VERSION 5.7 ;
BUSBITCHARS "[]" ;
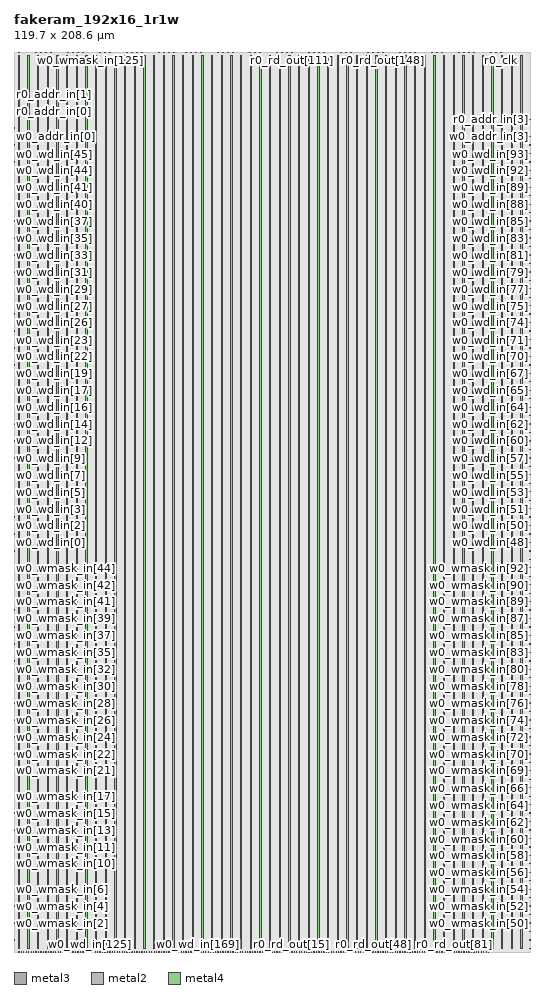
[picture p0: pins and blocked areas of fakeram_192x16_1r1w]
MACRO fakeram_192x16_1r1w
  FOREIGN fakeram_192x16_1r1w 0 0 ;
  SYMMETRY X Y R90 ;
  SIZE 119.700 BY 208.600 ;
  CLASS BLOCK ;
  PIN w0_wmask_in[0]
    DIRECTION INPUT ;
    USE SIGNAL ;
    SHAPE ABUTMENT ;
    PORT
      LAYER metal3 ;
      RECT 0.000 0.805 0.210 0.875 ;
    END
  END w0_wmask_in[0]
  PIN w0_wmask_in[1]
    DIRECTION INPUT ;
    USE SIGNAL ;
    SHAPE ABUTMENT ;
    PORT
      LAYER metal3 ;
      RECT 0.000 2.765 0.210 2.835 ;
    END
  END w0_wmask_in[1]
  PIN w0_wmask_in[2]
    DIRECTION INPUT ;
    USE SIGNAL ;
    SHAPE ABUTMENT ;
    PORT
      LAYER metal3 ;
      RECT 0.000 4.725 0.210 4.795 ;
    END
  END w0_wmask_in[2]
  PIN w0_wmask_in[3]
    DIRECTION INPUT ;
    USE SIGNAL ;
    SHAPE ABUTMENT ;
    PORT
      LAYER metal3 ;
      RECT 0.000 6.685 0.210 6.755 ;
    END
  END w0_wmask_in[3]
  PIN w0_wmask_in[4]
    DIRECTION INPUT ;
    USE SIGNAL ;
    SHAPE ABUTMENT ;
    PORT
      LAYER metal3 ;
      RECT 0.000 8.645 0.210 8.715 ;
    END
  END w0_wmask_in[4]
  PIN w0_wmask_in[5]
    DIRECTION INPUT ;
    USE SIGNAL ;
    SHAPE ABUTMENT ;
    PORT
      LAYER metal3 ;
      RECT 0.000 10.605 0.210 10.675 ;
    END
  END w0_wmask_in[5]
  PIN w0_wmask_in[6]
    DIRECTION INPUT ;
    USE SIGNAL ;
    SHAPE ABUTMENT ;
    PORT
      LAYER metal3 ;
      RECT 0.000 12.565 0.210 12.635 ;
    END
  END w0_wmask_in[6]
  PIN w0_wmask_in[7]
    DIRECTION INPUT ;
    USE SIGNAL ;
    SHAPE ABUTMENT ;
    PORT
      LAYER metal3 ;
      RECT 0.000 14.525 0.210 14.595 ;
    END
  END w0_wmask_in[7]
  PIN w0_wmask_in[8]
    DIRECTION INPUT ;
    USE SIGNAL ;
    SHAPE ABUTMENT ;
    PORT
      LAYER metal3 ;
      RECT 0.000 16.485 0.210 16.555 ;
    END
  END w0_wmask_in[8]
  PIN w0_wmask_in[9]
    DIRECTION INPUT ;
    USE SIGNAL ;
    SHAPE ABUTMENT ;
    PORT
      LAYER metal3 ;
      RECT 0.000 18.445 0.210 18.515 ;
    END
  END w0_wmask_in[9]
  PIN w0_wmask_in[10]
    DIRECTION INPUT ;
    USE SIGNAL ;
    SHAPE ABUTMENT ;
    PORT
      LAYER metal3 ;
      RECT 0.000 20.405 0.210 20.475 ;
    END
  END w0_wmask_in[10]
  PIN w0_wmask_in[11]
    DIRECTION INPUT ;
    USE SIGNAL ;
    SHAPE ABUTMENT ;
    PORT
      LAYER metal3 ;
      RECT 0.000 22.365 0.210 22.435 ;
    END
  END w0_wmask_in[11]
  PIN w0_wmask_in[12]
    DIRECTION INPUT ;
    USE SIGNAL ;
    SHAPE ABUTMENT ;
    PORT
      LAYER metal3 ;
      RECT 0.000 24.325 0.210 24.395 ;
    END
  END w0_wmask_in[12]
  PIN w0_wmask_in[13]
    DIRECTION INPUT ;
    USE SIGNAL ;
    SHAPE ABUTMENT ;
    PORT
      LAYER metal3 ;
      RECT 0.000 26.285 0.210 26.355 ;
    END
  END w0_wmask_in[13]
  PIN w0_wmask_in[14]
    DIRECTION INPUT ;
    USE SIGNAL ;
    SHAPE ABUTMENT ;
    PORT
      LAYER metal3 ;
      RECT 0.000 28.245 0.210 28.315 ;
    END
  END w0_wmask_in[14]
  PIN w0_wmask_in[15]
    DIRECTION INPUT ;
    USE SIGNAL ;
    SHAPE ABUTMENT ;
    PORT
      LAYER metal3 ;
      RECT 0.000 30.205 0.210 30.275 ;
    END
  END w0_wmask_in[15]
  PIN w0_wmask_in[16]
    DIRECTION INPUT ;
    USE SIGNAL ;
    SHAPE ABUTMENT ;
    PORT
      LAYER metal3 ;
      RECT 0.000 32.165 0.210 32.235 ;
    END
  END w0_wmask_in[16]
  PIN w0_wmask_in[17]
    DIRECTION INPUT ;
    USE SIGNAL ;
    SHAPE ABUTMENT ;
    PORT
      LAYER metal3 ;
      RECT 0.000 34.125 0.210 34.195 ;
    END
  END w0_wmask_in[17]
  PIN w0_wmask_in[18]
    DIRECTION INPUT ;
    USE SIGNAL ;
    SHAPE ABUTMENT ;
    PORT
      LAYER metal3 ;
      RECT 0.000 36.085 0.210 36.155 ;
    END
  END w0_wmask_in[18]
  PIN w0_wmask_in[19]
    DIRECTION INPUT ;
    USE SIGNAL ;
    SHAPE ABUTMENT ;
    PORT
      LAYER metal3 ;
      RECT 0.000 38.045 0.210 38.115 ;
    END
  END w0_wmask_in[19]
  PIN w0_wmask_in[20]
    DIRECTION INPUT ;
    USE SIGNAL ;
    SHAPE ABUTMENT ;
    PORT
      LAYER metal3 ;
      RECT 0.000 40.005 0.210 40.075 ;
    END
  END w0_wmask_in[20]
  PIN w0_wmask_in[21]
    DIRECTION INPUT ;
    USE SIGNAL ;
    SHAPE ABUTMENT ;
    PORT
      LAYER metal3 ;
      RECT 0.000 41.965 0.210 42.035 ;
    END
  END w0_wmask_in[21]
  PIN w0_wmask_in[22]
    DIRECTION INPUT ;
    USE SIGNAL ;
    SHAPE ABUTMENT ;
    PORT
      LAYER metal3 ;
      RECT 0.000 43.925 0.210 43.995 ;
    END
  END w0_wmask_in[22]
  PIN w0_wmask_in[23]
    DIRECTION INPUT ;
    USE SIGNAL ;
    SHAPE ABUTMENT ;
    PORT
      LAYER metal3 ;
      RECT 0.000 45.885 0.210 45.955 ;
    END
  END w0_wmask_in[23]
  PIN w0_wmask_in[24]
    DIRECTION INPUT ;
    USE SIGNAL ;
    SHAPE ABUTMENT ;
    PORT
      LAYER metal3 ;
      RECT 0.000 47.845 0.210 47.915 ;
    END
  END w0_wmask_in[24]
  PIN w0_wmask_in[25]
    DIRECTION INPUT ;
    USE SIGNAL ;
    SHAPE ABUTMENT ;
    PORT
      LAYER metal3 ;
      RECT 0.000 49.805 0.210 49.875 ;
    END
  END w0_wmask_in[25]
  PIN w0_wmask_in[26]
    DIRECTION INPUT ;
    USE SIGNAL ;
    SHAPE ABUTMENT ;
    PORT
      LAYER metal3 ;
      RECT 0.000 51.765 0.210 51.835 ;
    END
  END w0_wmask_in[26]
  PIN w0_wmask_in[27]
    DIRECTION INPUT ;
    USE SIGNAL ;
    SHAPE ABUTMENT ;
    PORT
      LAYER metal3 ;
      RECT 0.000 53.725 0.210 53.795 ;
    END
  END w0_wmask_in[27]
  PIN w0_wmask_in[28]
    DIRECTION INPUT ;
    USE SIGNAL ;
    SHAPE ABUTMENT ;
    PORT
      LAYER metal3 ;
      RECT 0.000 55.685 0.210 55.755 ;
    END
  END w0_wmask_in[28]
  PIN w0_wmask_in[29]
    DIRECTION INPUT ;
    USE SIGNAL ;
    SHAPE ABUTMENT ;
    PORT
      LAYER metal3 ;
      RECT 0.000 57.645 0.210 57.715 ;
    END
  END w0_wmask_in[29]
  PIN w0_wmask_in[30]
    DIRECTION INPUT ;
    USE SIGNAL ;
    SHAPE ABUTMENT ;
    PORT
      LAYER metal3 ;
      RECT 0.000 59.605 0.210 59.675 ;
    END
  END w0_wmask_in[30]
  PIN w0_wmask_in[31]
    DIRECTION INPUT ;
    USE SIGNAL ;
    SHAPE ABUTMENT ;
    PORT
      LAYER metal3 ;
      RECT 0.000 61.565 0.210 61.635 ;
    END
  END w0_wmask_in[31]
  PIN w0_wmask_in[32]
    DIRECTION INPUT ;
    USE SIGNAL ;
    SHAPE ABUTMENT ;
    PORT
      LAYER metal3 ;
      RECT 0.000 63.525 0.210 63.595 ;
    END
  END w0_wmask_in[32]
  PIN w0_wmask_in[33]
    DIRECTION INPUT ;
    USE SIGNAL ;
    SHAPE ABUTMENT ;
    PORT
      LAYER metal3 ;
      RECT 0.000 65.485 0.210 65.555 ;
    END
  END w0_wmask_in[33]
  PIN w0_wmask_in[34]
    DIRECTION INPUT ;
    USE SIGNAL ;
    SHAPE ABUTMENT ;
    PORT
      LAYER metal3 ;
      RECT 0.000 67.445 0.210 67.515 ;
    END
  END w0_wmask_in[34]
  PIN w0_wmask_in[35]
    DIRECTION INPUT ;
    USE SIGNAL ;
    SHAPE ABUTMENT ;
    PORT
      LAYER metal3 ;
      RECT 0.000 69.405 0.210 69.475 ;
    END
  END w0_wmask_in[35]
  PIN w0_wmask_in[36]
    DIRECTION INPUT ;
    USE SIGNAL ;
    SHAPE ABUTMENT ;
    PORT
      LAYER metal3 ;
      RECT 0.000 71.365 0.210 71.435 ;
    END
  END w0_wmask_in[36]
  PIN w0_wmask_in[37]
    DIRECTION INPUT ;
    USE SIGNAL ;
    SHAPE ABUTMENT ;
    PORT
      LAYER metal3 ;
      RECT 0.000 73.325 0.210 73.395 ;
    END
  END w0_wmask_in[37]
  PIN w0_wmask_in[38]
    DIRECTION INPUT ;
    USE SIGNAL ;
    SHAPE ABUTMENT ;
    PORT
      LAYER metal3 ;
      RECT 0.000 75.285 0.210 75.355 ;
    END
  END w0_wmask_in[38]
  PIN w0_wmask_in[39]
    DIRECTION INPUT ;
    USE SIGNAL ;
    SHAPE ABUTMENT ;
    PORT
      LAYER metal3 ;
      RECT 0.000 77.245 0.210 77.315 ;
    END
  END w0_wmask_in[39]
  PIN w0_wmask_in[40]
    DIRECTION INPUT ;
    USE SIGNAL ;
    SHAPE ABUTMENT ;
    PORT
      LAYER metal3 ;
      RECT 0.000 79.205 0.210 79.275 ;
    END
  END w0_wmask_in[40]
  PIN w0_wmask_in[41]
    DIRECTION INPUT ;
    USE SIGNAL ;
    SHAPE ABUTMENT ;
    PORT
      LAYER metal3 ;
      RECT 0.000 81.165 0.210 81.235 ;
    END
  END w0_wmask_in[41]
  PIN w0_wmask_in[42]
    DIRECTION INPUT ;
    USE SIGNAL ;
    SHAPE ABUTMENT ;
    PORT
      LAYER metal3 ;
      RECT 0.000 83.125 0.210 83.195 ;
    END
  END w0_wmask_in[42]
  PIN w0_wmask_in[43]
    DIRECTION INPUT ;
    USE SIGNAL ;
    SHAPE ABUTMENT ;
    PORT
      LAYER metal3 ;
      RECT 0.000 85.085 0.210 85.155 ;
    END
  END w0_wmask_in[43]
  PIN w0_wmask_in[44]
    DIRECTION INPUT ;
    USE SIGNAL ;
    SHAPE ABUTMENT ;
    PORT
      LAYER metal3 ;
      RECT 0.000 87.045 0.210 87.115 ;
    END
  END w0_wmask_in[44]
  PIN w0_wmask_in[45]
    DIRECTION INPUT ;
    USE SIGNAL ;
    SHAPE ABUTMENT ;
    PORT
      LAYER metal3 ;
      RECT 0.000 89.005 0.210 89.075 ;
    END
  END w0_wmask_in[45]
  PIN w0_wmask_in[46]
    DIRECTION INPUT ;
    USE SIGNAL ;
    SHAPE ABUTMENT ;
    PORT
      LAYER metal3 ;
      RECT 0.000 90.965 0.210 91.035 ;
    END
  END w0_wmask_in[46]
  PIN w0_wmask_in[47]
    DIRECTION INPUT ;
    USE SIGNAL ;
    SHAPE ABUTMENT ;
    PORT
      LAYER metal3 ;
      RECT 0.000 92.925 0.210 92.995 ;
    END
  END w0_wmask_in[47]
  PIN w0_wmask_in[48]
    DIRECTION INPUT ;
    USE SIGNAL ;
    SHAPE ABUTMENT ;
    PORT
      LAYER metal3 ;
      RECT 119.490 0.805 119.700 0.875 ;
    END
  END w0_wmask_in[48]
  PIN w0_wmask_in[49]
    DIRECTION INPUT ;
    USE SIGNAL ;
    SHAPE ABUTMENT ;
    PORT
      LAYER metal3 ;
      RECT 119.490 2.765 119.700 2.835 ;
    END
  END w0_wmask_in[49]
  PIN w0_wmask_in[50]
    DIRECTION INPUT ;
    USE SIGNAL ;
    SHAPE ABUTMENT ;
    PORT
      LAYER metal3 ;
      RECT 119.490 4.725 119.700 4.795 ;
    END
  END w0_wmask_in[50]
  PIN w0_wmask_in[51]
    DIRECTION INPUT ;
    USE SIGNAL ;
    SHAPE ABUTMENT ;
    PORT
      LAYER metal3 ;
      RECT 119.490 6.685 119.700 6.755 ;
    END
  END w0_wmask_in[51]
  PIN w0_wmask_in[52]
    DIRECTION INPUT ;
    USE SIGNAL ;
    SHAPE ABUTMENT ;
    PORT
      LAYER metal3 ;
      RECT 119.490 8.645 119.700 8.715 ;
    END
  END w0_wmask_in[52]
  PIN w0_wmask_in[53]
    DIRECTION INPUT ;
    USE SIGNAL ;
    SHAPE ABUTMENT ;
    PORT
      LAYER metal3 ;
      RECT 119.490 10.605 119.700 10.675 ;
    END
  END w0_wmask_in[53]
  PIN w0_wmask_in[54]
    DIRECTION INPUT ;
    USE SIGNAL ;
    SHAPE ABUTMENT ;
    PORT
      LAYER metal3 ;
      RECT 119.490 12.565 119.700 12.635 ;
    END
  END w0_wmask_in[54]
  PIN w0_wmask_in[55]
    DIRECTION INPUT ;
    USE SIGNAL ;
    SHAPE ABUTMENT ;
    PORT
      LAYER metal3 ;
      RECT 119.490 14.525 119.700 14.595 ;
    END
  END w0_wmask_in[55]
  PIN w0_wmask_in[56]
    DIRECTION INPUT ;
    USE SIGNAL ;
    SHAPE ABUTMENT ;
    PORT
      LAYER metal3 ;
      RECT 119.490 16.485 119.700 16.555 ;
    END
  END w0_wmask_in[56]
  PIN w0_wmask_in[57]
    DIRECTION INPUT ;
    USE SIGNAL ;
    SHAPE ABUTMENT ;
    PORT
      LAYER metal3 ;
      RECT 119.490 18.445 119.700 18.515 ;
    END
  END w0_wmask_in[57]
  PIN w0_wmask_in[58]
    DIRECTION INPUT ;
    USE SIGNAL ;
    SHAPE ABUTMENT ;
    PORT
      LAYER metal3 ;
      RECT 119.490 20.405 119.700 20.475 ;
    END
  END w0_wmask_in[58]
  PIN w0_wmask_in[59]
    DIRECTION INPUT ;
    USE SIGNAL ;
    SHAPE ABUTMENT ;
    PORT
      LAYER metal3 ;
      RECT 119.490 22.365 119.700 22.435 ;
    END
  END w0_wmask_in[59]
  PIN w0_wmask_in[60]
    DIRECTION INPUT ;
    USE SIGNAL ;
    SHAPE ABUTMENT ;
    PORT
      LAYER metal3 ;
      RECT 119.490 24.325 119.700 24.395 ;
    END
  END w0_wmask_in[60]
  PIN w0_wmask_in[61]
    DIRECTION INPUT ;
    USE SIGNAL ;
    SHAPE ABUTMENT ;
    PORT
      LAYER metal3 ;
      RECT 119.490 26.285 119.700 26.355 ;
    END
  END w0_wmask_in[61]
  PIN w0_wmask_in[62]
    DIRECTION INPUT ;
    USE SIGNAL ;
    SHAPE ABUTMENT ;
    PORT
      LAYER metal3 ;
      RECT 119.490 28.245 119.700 28.315 ;
    END
  END w0_wmask_in[62]
  PIN w0_wmask_in[63]
    DIRECTION INPUT ;
    USE SIGNAL ;
    SHAPE ABUTMENT ;
    PORT
      LAYER metal3 ;
      RECT 119.490 30.205 119.700 30.275 ;
    END
  END w0_wmask_in[63]
  PIN w0_wmask_in[64]
    DIRECTION INPUT ;
    USE SIGNAL ;
    SHAPE ABUTMENT ;
    PORT
      LAYER metal3 ;
      RECT 119.490 32.165 119.700 32.235 ;
    END
  END w0_wmask_in[64]
  PIN w0_wmask_in[65]
    DIRECTION INPUT ;
    USE SIGNAL ;
    SHAPE ABUTMENT ;
    PORT
      LAYER metal3 ;
      RECT 119.490 34.125 119.700 34.195 ;
    END
  END w0_wmask_in[65]
  PIN w0_wmask_in[66]
    DIRECTION INPUT ;
    USE SIGNAL ;
    SHAPE ABUTMENT ;
    PORT
      LAYER metal3 ;
      RECT 119.490 36.085 119.700 36.155 ;
    END
  END w0_wmask_in[66]
  PIN w0_wmask_in[67]
    DIRECTION INPUT ;
    USE SIGNAL ;
    SHAPE ABUTMENT ;
    PORT
      LAYER metal3 ;
      RECT 119.490 38.045 119.700 38.115 ;
    END
  END w0_wmask_in[67]
  PIN w0_wmask_in[68]
    DIRECTION INPUT ;
    USE SIGNAL ;
    SHAPE ABUTMENT ;
    PORT
      LAYER metal3 ;
      RECT 119.490 40.005 119.700 40.075 ;
    END
  END w0_wmask_in[68]
  PIN w0_wmask_in[69]
    DIRECTION INPUT ;
    USE SIGNAL ;
    SHAPE ABUTMENT ;
    PORT
      LAYER metal3 ;
      RECT 119.490 41.965 119.700 42.035 ;
    END
  END w0_wmask_in[69]
  PIN w0_wmask_in[70]
    DIRECTION INPUT ;
    USE SIGNAL ;
    SHAPE ABUTMENT ;
    PORT
      LAYER metal3 ;
      RECT 119.490 43.925 119.700 43.995 ;
    END
  END w0_wmask_in[70]
  PIN w0_wmask_in[71]
    DIRECTION INPUT ;
    USE SIGNAL ;
    SHAPE ABUTMENT ;
    PORT
      LAYER metal3 ;
      RECT 119.490 45.885 119.700 45.955 ;
    END
  END w0_wmask_in[71]
  PIN w0_wmask_in[72]
    DIRECTION INPUT ;
    USE SIGNAL ;
    SHAPE ABUTMENT ;
    PORT
      LAYER metal3 ;
      RECT 119.490 47.845 119.700 47.915 ;
    END
  END w0_wmask_in[72]
  PIN w0_wmask_in[73]
    DIRECTION INPUT ;
    USE SIGNAL ;
    SHAPE ABUTMENT ;
    PORT
      LAYER metal3 ;
      RECT 119.490 49.805 119.700 49.875 ;
    END
  END w0_wmask_in[73]
  PIN w0_wmask_in[74]
    DIRECTION INPUT ;
    USE SIGNAL ;
    SHAPE ABUTMENT ;
    PORT
      LAYER metal3 ;
      RECT 119.490 51.765 119.700 51.835 ;
    END
  END w0_wmask_in[74]
  PIN w0_wmask_in[75]
    DIRECTION INPUT ;
    USE SIGNAL ;
    SHAPE ABUTMENT ;
    PORT
      LAYER metal3 ;
      RECT 119.490 53.725 119.700 53.795 ;
    END
  END w0_wmask_in[75]
  PIN w0_wmask_in[76]
    DIRECTION INPUT ;
    USE SIGNAL ;
    SHAPE ABUTMENT ;
    PORT
      LAYER metal3 ;
      RECT 119.490 55.685 119.700 55.755 ;
    END
  END w0_wmask_in[76]
  PIN w0_wmask_in[77]
    DIRECTION INPUT ;
    USE SIGNAL ;
    SHAPE ABUTMENT ;
    PORT
      LAYER metal3 ;
      RECT 119.490 57.645 119.700 57.715 ;
    END
  END w0_wmask_in[77]
  PIN w0_wmask_in[78]
    DIRECTION INPUT ;
    USE SIGNAL ;
    SHAPE ABUTMENT ;
    PORT
      LAYER metal3 ;
      RECT 119.490 59.605 119.700 59.675 ;
    END
  END w0_wmask_in[78]
  PIN w0_wmask_in[79]
    DIRECTION INPUT ;
    USE SIGNAL ;
    SHAPE ABUTMENT ;
    PORT
      LAYER metal3 ;
      RECT 119.490 61.565 119.700 61.635 ;
    END
  END w0_wmask_in[79]
  PIN w0_wmask_in[80]
    DIRECTION INPUT ;
    USE SIGNAL ;
    SHAPE ABUTMENT ;
    PORT
      LAYER metal3 ;
      RECT 119.490 63.525 119.700 63.595 ;
    END
  END w0_wmask_in[80]
  PIN w0_wmask_in[81]
    DIRECTION INPUT ;
    USE SIGNAL ;
    SHAPE ABUTMENT ;
    PORT
      LAYER metal3 ;
      RECT 119.490 65.485 119.700 65.555 ;
    END
  END w0_wmask_in[81]
  PIN w0_wmask_in[82]
    DIRECTION INPUT ;
    USE SIGNAL ;
    SHAPE ABUTMENT ;
    PORT
      LAYER metal3 ;
      RECT 119.490 67.445 119.700 67.515 ;
    END
  END w0_wmask_in[82]
  PIN w0_wmask_in[83]
    DIRECTION INPUT ;
    USE SIGNAL ;
    SHAPE ABUTMENT ;
    PORT
      LAYER metal3 ;
      RECT 119.490 69.405 119.700 69.475 ;
    END
  END w0_wmask_in[83]
  PIN w0_wmask_in[84]
    DIRECTION INPUT ;
    USE SIGNAL ;
    SHAPE ABUTMENT ;
    PORT
      LAYER metal3 ;
      RECT 119.490 71.365 119.700 71.435 ;
    END
  END w0_wmask_in[84]
  PIN w0_wmask_in[85]
    DIRECTION INPUT ;
    USE SIGNAL ;
    SHAPE ABUTMENT ;
    PORT
      LAYER metal3 ;
      RECT 119.490 73.325 119.700 73.395 ;
    END
  END w0_wmask_in[85]
  PIN w0_wmask_in[86]
    DIRECTION INPUT ;
    USE SIGNAL ;
    SHAPE ABUTMENT ;
    PORT
      LAYER metal3 ;
      RECT 119.490 75.285 119.700 75.355 ;
    END
  END w0_wmask_in[86]
  PIN w0_wmask_in[87]
    DIRECTION INPUT ;
    USE SIGNAL ;
    SHAPE ABUTMENT ;
    PORT
      LAYER metal3 ;
      RECT 119.490 77.245 119.700 77.315 ;
    END
  END w0_wmask_in[87]
  PIN w0_wmask_in[88]
    DIRECTION INPUT ;
    USE SIGNAL ;
    SHAPE ABUTMENT ;
    PORT
      LAYER metal3 ;
      RECT 119.490 79.205 119.700 79.275 ;
    END
  END w0_wmask_in[88]
  PIN w0_wmask_in[89]
    DIRECTION INPUT ;
    USE SIGNAL ;
    SHAPE ABUTMENT ;
    PORT
      LAYER metal3 ;
      RECT 119.490 81.165 119.700 81.235 ;
    END
  END w0_wmask_in[89]
  PIN w0_wmask_in[90]
    DIRECTION INPUT ;
    USE SIGNAL ;
    SHAPE ABUTMENT ;
    PORT
      LAYER metal3 ;
      RECT 119.490 83.125 119.700 83.195 ;
    END
  END w0_wmask_in[90]
  PIN w0_wmask_in[91]
    DIRECTION INPUT ;
    USE SIGNAL ;
    SHAPE ABUTMENT ;
    PORT
      LAYER metal3 ;
      RECT 119.490 85.085 119.700 85.155 ;
    END
  END w0_wmask_in[91]
  PIN w0_wmask_in[92]
    DIRECTION INPUT ;
    USE SIGNAL ;
    SHAPE ABUTMENT ;
    PORT
      LAYER metal3 ;
      RECT 119.490 87.045 119.700 87.115 ;
    END
  END w0_wmask_in[92]
  PIN w0_wmask_in[93]
    DIRECTION INPUT ;
    USE SIGNAL ;
    SHAPE ABUTMENT ;
    PORT
      LAYER metal3 ;
      RECT 119.490 89.005 119.700 89.075 ;
    END
  END w0_wmask_in[93]
  PIN w0_wmask_in[94]
    DIRECTION INPUT ;
    USE SIGNAL ;
    SHAPE ABUTMENT ;
    PORT
      LAYER metal3 ;
      RECT 119.490 90.965 119.700 91.035 ;
    END
  END w0_wmask_in[94]
  PIN w0_wmask_in[95]
    DIRECTION INPUT ;
    USE SIGNAL ;
    SHAPE ABUTMENT ;
    PORT
      LAYER metal3 ;
      RECT 119.490 92.925 119.700 92.995 ;
    END
  END w0_wmask_in[95]
  PIN w0_wmask_in[96]
    DIRECTION INPUT ;
    USE SIGNAL ;
    SHAPE ABUTMENT ;
    PORT
      LAYER metal2 ;
      RECT 1.105 208.390 1.175 208.600 ;
    END
  END w0_wmask_in[96]
  PIN w0_wmask_in[97]
    DIRECTION INPUT ;
    USE SIGNAL ;
    SHAPE ABUTMENT ;
    PORT
      LAYER metal2 ;
      RECT 1.675 208.390 1.745 208.600 ;
    END
  END w0_wmask_in[97]
  PIN w0_wmask_in[98]
    DIRECTION INPUT ;
    USE SIGNAL ;
    SHAPE ABUTMENT ;
    PORT
      LAYER metal2 ;
      RECT 2.245 208.390 2.315 208.600 ;
    END
  END w0_wmask_in[98]
  PIN w0_wmask_in[99]
    DIRECTION INPUT ;
    USE SIGNAL ;
    SHAPE ABUTMENT ;
    PORT
      LAYER metal2 ;
      RECT 2.815 208.390 2.885 208.600 ;
    END
  END w0_wmask_in[99]
  PIN w0_wmask_in[100]
    DIRECTION INPUT ;
    USE SIGNAL ;
    SHAPE ABUTMENT ;
    PORT
      LAYER metal2 ;
      RECT 3.385 208.390 3.455 208.600 ;
    END
  END w0_wmask_in[100]
  PIN w0_wmask_in[101]
    DIRECTION INPUT ;
    USE SIGNAL ;
    SHAPE ABUTMENT ;
    PORT
      LAYER metal2 ;
      RECT 3.955 208.390 4.025 208.600 ;
    END
  END w0_wmask_in[101]
  PIN w0_wmask_in[102]
    DIRECTION INPUT ;
    USE SIGNAL ;
    SHAPE ABUTMENT ;
    PORT
      LAYER metal2 ;
      RECT 4.525 208.390 4.595 208.600 ;
    END
  END w0_wmask_in[102]
  PIN w0_wmask_in[103]
    DIRECTION INPUT ;
    USE SIGNAL ;
    SHAPE ABUTMENT ;
    PORT
      LAYER metal2 ;
      RECT 5.095 208.390 5.165 208.600 ;
    END
  END w0_wmask_in[103]
  PIN w0_wmask_in[104]
    DIRECTION INPUT ;
    USE SIGNAL ;
    SHAPE ABUTMENT ;
    PORT
      LAYER metal2 ;
      RECT 5.665 208.390 5.735 208.600 ;
    END
  END w0_wmask_in[104]
  PIN w0_wmask_in[105]
    DIRECTION INPUT ;
    USE SIGNAL ;
    SHAPE ABUTMENT ;
    PORT
      LAYER metal2 ;
      RECT 6.235 208.390 6.305 208.600 ;
    END
  END w0_wmask_in[105]
  PIN w0_wmask_in[106]
    DIRECTION INPUT ;
    USE SIGNAL ;
    SHAPE ABUTMENT ;
    PORT
      LAYER metal2 ;
      RECT 6.805 208.390 6.875 208.600 ;
    END
  END w0_wmask_in[106]
  PIN w0_wmask_in[107]
    DIRECTION INPUT ;
    USE SIGNAL ;
    SHAPE ABUTMENT ;
    PORT
      LAYER metal2 ;
      RECT 7.375 208.390 7.445 208.600 ;
    END
  END w0_wmask_in[107]
  PIN w0_wmask_in[108]
    DIRECTION INPUT ;
    USE SIGNAL ;
    SHAPE ABUTMENT ;
    PORT
      LAYER metal2 ;
      RECT 7.945 208.390 8.015 208.600 ;
    END
  END w0_wmask_in[108]
  PIN w0_wmask_in[109]
    DIRECTION INPUT ;
    USE SIGNAL ;
    SHAPE ABUTMENT ;
    PORT
      LAYER metal2 ;
      RECT 8.515 208.390 8.585 208.600 ;
    END
  END w0_wmask_in[109]
  PIN w0_wmask_in[110]
    DIRECTION INPUT ;
    USE SIGNAL ;
    SHAPE ABUTMENT ;
    PORT
      LAYER metal2 ;
      RECT 9.085 208.390 9.155 208.600 ;
    END
  END w0_wmask_in[110]
  PIN w0_wmask_in[111]
    DIRECTION INPUT ;
    USE SIGNAL ;
    SHAPE ABUTMENT ;
    PORT
      LAYER metal2 ;
      RECT 9.655 208.390 9.725 208.600 ;
    END
  END w0_wmask_in[111]
  PIN w0_wmask_in[112]
    DIRECTION INPUT ;
    USE SIGNAL ;
    SHAPE ABUTMENT ;
    PORT
      LAYER metal2 ;
      RECT 10.225 208.390 10.295 208.600 ;
    END
  END w0_wmask_in[112]
  PIN w0_wmask_in[113]
    DIRECTION INPUT ;
    USE SIGNAL ;
    SHAPE ABUTMENT ;
    PORT
      LAYER metal2 ;
      RECT 10.795 208.390 10.865 208.600 ;
    END
  END w0_wmask_in[113]
  PIN w0_wmask_in[114]
    DIRECTION INPUT ;
    USE SIGNAL ;
    SHAPE ABUTMENT ;
    PORT
      LAYER metal2 ;
      RECT 11.365 208.390 11.435 208.600 ;
    END
  END w0_wmask_in[114]
  PIN w0_wmask_in[115]
    DIRECTION INPUT ;
    USE SIGNAL ;
    SHAPE ABUTMENT ;
    PORT
      LAYER metal2 ;
      RECT 11.935 208.390 12.005 208.600 ;
    END
  END w0_wmask_in[115]
  PIN w0_wmask_in[116]
    DIRECTION INPUT ;
    USE SIGNAL ;
    SHAPE ABUTMENT ;
    PORT
      LAYER metal2 ;
      RECT 12.505 208.390 12.575 208.600 ;
    END
  END w0_wmask_in[116]
  PIN w0_wmask_in[117]
    DIRECTION INPUT ;
    USE SIGNAL ;
    SHAPE ABUTMENT ;
    PORT
      LAYER metal2 ;
      RECT 13.075 208.390 13.145 208.600 ;
    END
  END w0_wmask_in[117]
  PIN w0_wmask_in[118]
    DIRECTION INPUT ;
    USE SIGNAL ;
    SHAPE ABUTMENT ;
    PORT
      LAYER metal2 ;
      RECT 13.645 208.390 13.715 208.600 ;
    END
  END w0_wmask_in[118]
  PIN w0_wmask_in[119]
    DIRECTION INPUT ;
    USE SIGNAL ;
    SHAPE ABUTMENT ;
    PORT
      LAYER metal2 ;
      RECT 14.215 208.390 14.285 208.600 ;
    END
  END w0_wmask_in[119]
  PIN w0_wmask_in[120]
    DIRECTION INPUT ;
    USE SIGNAL ;
    SHAPE ABUTMENT ;
    PORT
      LAYER metal2 ;
      RECT 14.785 208.390 14.855 208.600 ;
    END
  END w0_wmask_in[120]
  PIN w0_wmask_in[121]
    DIRECTION INPUT ;
    USE SIGNAL ;
    SHAPE ABUTMENT ;
    PORT
      LAYER metal2 ;
      RECT 15.355 208.390 15.425 208.600 ;
    END
  END w0_wmask_in[121]
  PIN w0_wmask_in[122]
    DIRECTION INPUT ;
    USE SIGNAL ;
    SHAPE ABUTMENT ;
    PORT
      LAYER metal2 ;
      RECT 15.925 208.390 15.995 208.600 ;
    END
  END w0_wmask_in[122]
  PIN w0_wmask_in[123]
    DIRECTION INPUT ;
    USE SIGNAL ;
    SHAPE ABUTMENT ;
    PORT
      LAYER metal2 ;
      RECT 16.495 208.390 16.565 208.600 ;
    END
  END w0_wmask_in[123]
  PIN w0_wmask_in[124]
    DIRECTION INPUT ;
    USE SIGNAL ;
    SHAPE ABUTMENT ;
    PORT
      LAYER metal2 ;
      RECT 17.065 208.390 17.135 208.600 ;
    END
  END w0_wmask_in[124]
  PIN w0_wmask_in[125]
    DIRECTION INPUT ;
    USE SIGNAL ;
    SHAPE ABUTMENT ;
    PORT
      LAYER metal2 ;
      RECT 17.635 208.390 17.705 208.600 ;
    END
  END w0_wmask_in[125]
  PIN w0_wmask_in[126]
    DIRECTION INPUT ;
    USE SIGNAL ;
    SHAPE ABUTMENT ;
    PORT
      LAYER metal2 ;
      RECT 18.205 208.390 18.275 208.600 ;
    END
  END w0_wmask_in[126]
  PIN w0_wmask_in[127]
    DIRECTION INPUT ;
    USE SIGNAL ;
    SHAPE ABUTMENT ;
    PORT
      LAYER metal2 ;
      RECT 18.775 208.390 18.845 208.600 ;
    END
  END w0_wmask_in[127]
  PIN w0_wmask_in[128]
    DIRECTION INPUT ;
    USE SIGNAL ;
    SHAPE ABUTMENT ;
    PORT
      LAYER metal2 ;
      RECT 19.345 208.390 19.415 208.600 ;
    END
  END w0_wmask_in[128]
  PIN w0_wmask_in[129]
    DIRECTION INPUT ;
    USE SIGNAL ;
    SHAPE ABUTMENT ;
    PORT
      LAYER metal2 ;
      RECT 19.915 208.390 19.985 208.600 ;
    END
  END w0_wmask_in[129]
  PIN w0_wmask_in[130]
    DIRECTION INPUT ;
    USE SIGNAL ;
    SHAPE ABUTMENT ;
    PORT
      LAYER metal2 ;
      RECT 20.485 208.390 20.555 208.600 ;
    END
  END w0_wmask_in[130]
  PIN w0_wmask_in[131]
    DIRECTION INPUT ;
    USE SIGNAL ;
    SHAPE ABUTMENT ;
    PORT
      LAYER metal2 ;
      RECT 21.055 208.390 21.125 208.600 ;
    END
  END w0_wmask_in[131]
  PIN w0_wmask_in[132]
    DIRECTION INPUT ;
    USE SIGNAL ;
    SHAPE ABUTMENT ;
    PORT
      LAYER metal2 ;
      RECT 21.625 208.390 21.695 208.600 ;
    END
  END w0_wmask_in[132]
  PIN w0_wmask_in[133]
    DIRECTION INPUT ;
    USE SIGNAL ;
    SHAPE ABUTMENT ;
    PORT
      LAYER metal2 ;
      RECT 22.195 208.390 22.265 208.600 ;
    END
  END w0_wmask_in[133]
  PIN w0_wmask_in[134]
    DIRECTION INPUT ;
    USE SIGNAL ;
    SHAPE ABUTMENT ;
    PORT
      LAYER metal2 ;
      RECT 22.765 208.390 22.835 208.600 ;
    END
  END w0_wmask_in[134]
  PIN w0_wmask_in[135]
    DIRECTION INPUT ;
    USE SIGNAL ;
    SHAPE ABUTMENT ;
    PORT
      LAYER metal2 ;
      RECT 23.335 208.390 23.405 208.600 ;
    END
  END w0_wmask_in[135]
  PIN w0_wmask_in[136]
    DIRECTION INPUT ;
    USE SIGNAL ;
    SHAPE ABUTMENT ;
    PORT
      LAYER metal2 ;
      RECT 23.905 208.390 23.975 208.600 ;
    END
  END w0_wmask_in[136]
  PIN w0_wmask_in[137]
    DIRECTION INPUT ;
    USE SIGNAL ;
    SHAPE ABUTMENT ;
    PORT
      LAYER metal2 ;
      RECT 24.475 208.390 24.545 208.600 ;
    END
  END w0_wmask_in[137]
  PIN w0_wmask_in[138]
    DIRECTION INPUT ;
    USE SIGNAL ;
    SHAPE ABUTMENT ;
    PORT
      LAYER metal2 ;
      RECT 25.045 208.390 25.115 208.600 ;
    END
  END w0_wmask_in[138]
  PIN w0_wmask_in[139]
    DIRECTION INPUT ;
    USE SIGNAL ;
    SHAPE ABUTMENT ;
    PORT
      LAYER metal2 ;
      RECT 25.615 208.390 25.685 208.600 ;
    END
  END w0_wmask_in[139]
  PIN w0_wmask_in[140]
    DIRECTION INPUT ;
    USE SIGNAL ;
    SHAPE ABUTMENT ;
    PORT
      LAYER metal2 ;
      RECT 26.185 208.390 26.255 208.600 ;
    END
  END w0_wmask_in[140]
  PIN w0_wmask_in[141]
    DIRECTION INPUT ;
    USE SIGNAL ;
    SHAPE ABUTMENT ;
    PORT
      LAYER metal2 ;
      RECT 26.755 208.390 26.825 208.600 ;
    END
  END w0_wmask_in[141]
  PIN w0_wmask_in[142]
    DIRECTION INPUT ;
    USE SIGNAL ;
    SHAPE ABUTMENT ;
    PORT
      LAYER metal2 ;
      RECT 27.325 208.390 27.395 208.600 ;
    END
  END w0_wmask_in[142]
  PIN w0_wmask_in[143]
    DIRECTION INPUT ;
    USE SIGNAL ;
    SHAPE ABUTMENT ;
    PORT
      LAYER metal2 ;
      RECT 27.895 208.390 27.965 208.600 ;
    END
  END w0_wmask_in[143]
  PIN w0_wmask_in[144]
    DIRECTION INPUT ;
    USE SIGNAL ;
    SHAPE ABUTMENT ;
    PORT
      LAYER metal2 ;
      RECT 28.465 208.390 28.535 208.600 ;
    END
  END w0_wmask_in[144]
  PIN w0_wmask_in[145]
    DIRECTION INPUT ;
    USE SIGNAL ;
    SHAPE ABUTMENT ;
    PORT
      LAYER metal2 ;
      RECT 29.035 208.390 29.105 208.600 ;
    END
  END w0_wmask_in[145]
  PIN w0_wmask_in[146]
    DIRECTION INPUT ;
    USE SIGNAL ;
    SHAPE ABUTMENT ;
    PORT
      LAYER metal2 ;
      RECT 29.605 208.390 29.675 208.600 ;
    END
  END w0_wmask_in[146]
  PIN w0_wmask_in[147]
    DIRECTION INPUT ;
    USE SIGNAL ;
    SHAPE ABUTMENT ;
    PORT
      LAYER metal2 ;
      RECT 30.175 208.390 30.245 208.600 ;
    END
  END w0_wmask_in[147]
  PIN w0_wmask_in[148]
    DIRECTION INPUT ;
    USE SIGNAL ;
    SHAPE ABUTMENT ;
    PORT
      LAYER metal2 ;
      RECT 30.745 208.390 30.815 208.600 ;
    END
  END w0_wmask_in[148]
  PIN w0_wmask_in[149]
    DIRECTION INPUT ;
    USE SIGNAL ;
    SHAPE ABUTMENT ;
    PORT
      LAYER metal2 ;
      RECT 31.315 208.390 31.385 208.600 ;
    END
  END w0_wmask_in[149]
  PIN w0_wmask_in[150]
    DIRECTION INPUT ;
    USE SIGNAL ;
    SHAPE ABUTMENT ;
    PORT
      LAYER metal2 ;
      RECT 31.885 208.390 31.955 208.600 ;
    END
  END w0_wmask_in[150]
  PIN w0_wmask_in[151]
    DIRECTION INPUT ;
    USE SIGNAL ;
    SHAPE ABUTMENT ;
    PORT
      LAYER metal2 ;
      RECT 32.455 208.390 32.525 208.600 ;
    END
  END w0_wmask_in[151]
  PIN w0_wmask_in[152]
    DIRECTION INPUT ;
    USE SIGNAL ;
    SHAPE ABUTMENT ;
    PORT
      LAYER metal2 ;
      RECT 33.025 208.390 33.095 208.600 ;
    END
  END w0_wmask_in[152]
  PIN w0_wmask_in[153]
    DIRECTION INPUT ;
    USE SIGNAL ;
    SHAPE ABUTMENT ;
    PORT
      LAYER metal2 ;
      RECT 33.595 208.390 33.665 208.600 ;
    END
  END w0_wmask_in[153]
  PIN w0_wmask_in[154]
    DIRECTION INPUT ;
    USE SIGNAL ;
    SHAPE ABUTMENT ;
    PORT
      LAYER metal2 ;
      RECT 34.165 208.390 34.235 208.600 ;
    END
  END w0_wmask_in[154]
  PIN w0_wmask_in[155]
    DIRECTION INPUT ;
    USE SIGNAL ;
    SHAPE ABUTMENT ;
    PORT
      LAYER metal2 ;
      RECT 34.735 208.390 34.805 208.600 ;
    END
  END w0_wmask_in[155]
  PIN w0_wmask_in[156]
    DIRECTION INPUT ;
    USE SIGNAL ;
    SHAPE ABUTMENT ;
    PORT
      LAYER metal2 ;
      RECT 35.305 208.390 35.375 208.600 ;
    END
  END w0_wmask_in[156]
  PIN w0_wmask_in[157]
    DIRECTION INPUT ;
    USE SIGNAL ;
    SHAPE ABUTMENT ;
    PORT
      LAYER metal2 ;
      RECT 35.875 208.390 35.945 208.600 ;
    END
  END w0_wmask_in[157]
  PIN w0_wmask_in[158]
    DIRECTION INPUT ;
    USE SIGNAL ;
    SHAPE ABUTMENT ;
    PORT
      LAYER metal2 ;
      RECT 36.445 208.390 36.515 208.600 ;
    END
  END w0_wmask_in[158]
  PIN w0_wmask_in[159]
    DIRECTION INPUT ;
    USE SIGNAL ;
    SHAPE ABUTMENT ;
    PORT
      LAYER metal2 ;
      RECT 37.015 208.390 37.085 208.600 ;
    END
  END w0_wmask_in[159]
  PIN w0_wmask_in[160]
    DIRECTION INPUT ;
    USE SIGNAL ;
    SHAPE ABUTMENT ;
    PORT
      LAYER metal2 ;
      RECT 37.585 208.390 37.655 208.600 ;
    END
  END w0_wmask_in[160]
  PIN w0_wmask_in[161]
    DIRECTION INPUT ;
    USE SIGNAL ;
    SHAPE ABUTMENT ;
    PORT
      LAYER metal2 ;
      RECT 38.155 208.390 38.225 208.600 ;
    END
  END w0_wmask_in[161]
  PIN w0_wmask_in[162]
    DIRECTION INPUT ;
    USE SIGNAL ;
    SHAPE ABUTMENT ;
    PORT
      LAYER metal2 ;
      RECT 38.725 208.390 38.795 208.600 ;
    END
  END w0_wmask_in[162]
  PIN w0_wmask_in[163]
    DIRECTION INPUT ;
    USE SIGNAL ;
    SHAPE ABUTMENT ;
    PORT
      LAYER metal2 ;
      RECT 39.295 208.390 39.365 208.600 ;
    END
  END w0_wmask_in[163]
  PIN w0_wmask_in[164]
    DIRECTION INPUT ;
    USE SIGNAL ;
    SHAPE ABUTMENT ;
    PORT
      LAYER metal2 ;
      RECT 39.865 208.390 39.935 208.600 ;
    END
  END w0_wmask_in[164]
  PIN w0_wmask_in[165]
    DIRECTION INPUT ;
    USE SIGNAL ;
    SHAPE ABUTMENT ;
    PORT
      LAYER metal2 ;
      RECT 40.435 208.390 40.505 208.600 ;
    END
  END w0_wmask_in[165]
  PIN w0_wmask_in[166]
    DIRECTION INPUT ;
    USE SIGNAL ;
    SHAPE ABUTMENT ;
    PORT
      LAYER metal2 ;
      RECT 41.005 208.390 41.075 208.600 ;
    END
  END w0_wmask_in[166]
  PIN w0_wmask_in[167]
    DIRECTION INPUT ;
    USE SIGNAL ;
    SHAPE ABUTMENT ;
    PORT
      LAYER metal2 ;
      RECT 41.575 208.390 41.645 208.600 ;
    END
  END w0_wmask_in[167]
  PIN w0_wmask_in[168]
    DIRECTION INPUT ;
    USE SIGNAL ;
    SHAPE ABUTMENT ;
    PORT
      LAYER metal2 ;
      RECT 42.145 208.390 42.215 208.600 ;
    END
  END w0_wmask_in[168]
  PIN w0_wmask_in[169]
    DIRECTION INPUT ;
    USE SIGNAL ;
    SHAPE ABUTMENT ;
    PORT
      LAYER metal2 ;
      RECT 42.715 208.390 42.785 208.600 ;
    END
  END w0_wmask_in[169]
  PIN w0_wmask_in[170]
    DIRECTION INPUT ;
    USE SIGNAL ;
    SHAPE ABUTMENT ;
    PORT
      LAYER metal2 ;
      RECT 43.285 208.390 43.355 208.600 ;
    END
  END w0_wmask_in[170]
  PIN w0_wmask_in[171]
    DIRECTION INPUT ;
    USE SIGNAL ;
    SHAPE ABUTMENT ;
    PORT
      LAYER metal2 ;
      RECT 43.855 208.390 43.925 208.600 ;
    END
  END w0_wmask_in[171]
  PIN w0_wmask_in[172]
    DIRECTION INPUT ;
    USE SIGNAL ;
    SHAPE ABUTMENT ;
    PORT
      LAYER metal2 ;
      RECT 44.425 208.390 44.495 208.600 ;
    END
  END w0_wmask_in[172]
  PIN w0_wmask_in[173]
    DIRECTION INPUT ;
    USE SIGNAL ;
    SHAPE ABUTMENT ;
    PORT
      LAYER metal2 ;
      RECT 44.995 208.390 45.065 208.600 ;
    END
  END w0_wmask_in[173]
  PIN w0_wmask_in[174]
    DIRECTION INPUT ;
    USE SIGNAL ;
    SHAPE ABUTMENT ;
    PORT
      LAYER metal2 ;
      RECT 45.565 208.390 45.635 208.600 ;
    END
  END w0_wmask_in[174]
  PIN w0_wmask_in[175]
    DIRECTION INPUT ;
    USE SIGNAL ;
    SHAPE ABUTMENT ;
    PORT
      LAYER metal2 ;
      RECT 46.135 208.390 46.205 208.600 ;
    END
  END w0_wmask_in[175]
  PIN w0_wmask_in[176]
    DIRECTION INPUT ;
    USE SIGNAL ;
    SHAPE ABUTMENT ;
    PORT
      LAYER metal2 ;
      RECT 46.705 208.390 46.775 208.600 ;
    END
  END w0_wmask_in[176]
  PIN w0_wmask_in[177]
    DIRECTION INPUT ;
    USE SIGNAL ;
    SHAPE ABUTMENT ;
    PORT
      LAYER metal2 ;
      RECT 47.275 208.390 47.345 208.600 ;
    END
  END w0_wmask_in[177]
  PIN w0_wmask_in[178]
    DIRECTION INPUT ;
    USE SIGNAL ;
    SHAPE ABUTMENT ;
    PORT
      LAYER metal2 ;
      RECT 47.845 208.390 47.915 208.600 ;
    END
  END w0_wmask_in[178]
  PIN w0_wmask_in[179]
    DIRECTION INPUT ;
    USE SIGNAL ;
    SHAPE ABUTMENT ;
    PORT
      LAYER metal2 ;
      RECT 48.415 208.390 48.485 208.600 ;
    END
  END w0_wmask_in[179]
  PIN w0_wmask_in[180]
    DIRECTION INPUT ;
    USE SIGNAL ;
    SHAPE ABUTMENT ;
    PORT
      LAYER metal2 ;
      RECT 48.985 208.390 49.055 208.600 ;
    END
  END w0_wmask_in[180]
  PIN w0_wmask_in[181]
    DIRECTION INPUT ;
    USE SIGNAL ;
    SHAPE ABUTMENT ;
    PORT
      LAYER metal2 ;
      RECT 49.555 208.390 49.625 208.600 ;
    END
  END w0_wmask_in[181]
  PIN w0_wmask_in[182]
    DIRECTION INPUT ;
    USE SIGNAL ;
    SHAPE ABUTMENT ;
    PORT
      LAYER metal2 ;
      RECT 50.125 208.390 50.195 208.600 ;
    END
  END w0_wmask_in[182]
  PIN w0_wmask_in[183]
    DIRECTION INPUT ;
    USE SIGNAL ;
    SHAPE ABUTMENT ;
    PORT
      LAYER metal2 ;
      RECT 50.695 208.390 50.765 208.600 ;
    END
  END w0_wmask_in[183]
  PIN w0_wmask_in[184]
    DIRECTION INPUT ;
    USE SIGNAL ;
    SHAPE ABUTMENT ;
    PORT
      LAYER metal2 ;
      RECT 51.265 208.390 51.335 208.600 ;
    END
  END w0_wmask_in[184]
  PIN w0_wmask_in[185]
    DIRECTION INPUT ;
    USE SIGNAL ;
    SHAPE ABUTMENT ;
    PORT
      LAYER metal2 ;
      RECT 51.835 208.390 51.905 208.600 ;
    END
  END w0_wmask_in[185]
  PIN w0_wmask_in[186]
    DIRECTION INPUT ;
    USE SIGNAL ;
    SHAPE ABUTMENT ;
    PORT
      LAYER metal2 ;
      RECT 52.405 208.390 52.475 208.600 ;
    END
  END w0_wmask_in[186]
  PIN w0_wmask_in[187]
    DIRECTION INPUT ;
    USE SIGNAL ;
    SHAPE ABUTMENT ;
    PORT
      LAYER metal2 ;
      RECT 52.975 208.390 53.045 208.600 ;
    END
  END w0_wmask_in[187]
  PIN w0_wmask_in[188]
    DIRECTION INPUT ;
    USE SIGNAL ;
    SHAPE ABUTMENT ;
    PORT
      LAYER metal2 ;
      RECT 53.545 208.390 53.615 208.600 ;
    END
  END w0_wmask_in[188]
  PIN w0_wmask_in[189]
    DIRECTION INPUT ;
    USE SIGNAL ;
    SHAPE ABUTMENT ;
    PORT
      LAYER metal2 ;
      RECT 54.115 208.390 54.185 208.600 ;
    END
  END w0_wmask_in[189]
  PIN w0_wmask_in[190]
    DIRECTION INPUT ;
    USE SIGNAL ;
    SHAPE ABUTMENT ;
    PORT
      LAYER metal2 ;
      RECT 54.685 208.390 54.755 208.600 ;
    END
  END w0_wmask_in[190]
  PIN w0_wmask_in[191]
    DIRECTION INPUT ;
    USE SIGNAL ;
    SHAPE ABUTMENT ;
    PORT
      LAYER metal2 ;
      RECT 55.255 208.390 55.325 208.600 ;
    END
  END w0_wmask_in[191]
  PIN w0_wd_in[0]
    DIRECTION INPUT ;
    USE SIGNAL ;
    SHAPE ABUTMENT ;
    PORT
      LAYER metal3 ;
      RECT 0.000 94.885 0.210 94.955 ;
    END
  END w0_wd_in[0]
  PIN w0_wd_in[1]
    DIRECTION INPUT ;
    USE SIGNAL ;
    SHAPE ABUTMENT ;
    PORT
      LAYER metal3 ;
      RECT 0.000 96.845 0.210 96.915 ;
    END
  END w0_wd_in[1]
  PIN w0_wd_in[2]
    DIRECTION INPUT ;
    USE SIGNAL ;
    SHAPE ABUTMENT ;
    PORT
      LAYER metal3 ;
      RECT 0.000 98.805 0.210 98.875 ;
    END
  END w0_wd_in[2]
  PIN w0_wd_in[3]
    DIRECTION INPUT ;
    USE SIGNAL ;
    SHAPE ABUTMENT ;
    PORT
      LAYER metal3 ;
      RECT 0.000 100.765 0.210 100.835 ;
    END
  END w0_wd_in[3]
  PIN w0_wd_in[4]
    DIRECTION INPUT ;
    USE SIGNAL ;
    SHAPE ABUTMENT ;
    PORT
      LAYER metal3 ;
      RECT 0.000 102.725 0.210 102.795 ;
    END
  END w0_wd_in[4]
  PIN w0_wd_in[5]
    DIRECTION INPUT ;
    USE SIGNAL ;
    SHAPE ABUTMENT ;
    PORT
      LAYER metal3 ;
      RECT 0.000 104.685 0.210 104.755 ;
    END
  END w0_wd_in[5]
  PIN w0_wd_in[6]
    DIRECTION INPUT ;
    USE SIGNAL ;
    SHAPE ABUTMENT ;
    PORT
      LAYER metal3 ;
      RECT 0.000 106.645 0.210 106.715 ;
    END
  END w0_wd_in[6]
  PIN w0_wd_in[7]
    DIRECTION INPUT ;
    USE SIGNAL ;
    SHAPE ABUTMENT ;
    PORT
      LAYER metal3 ;
      RECT 0.000 108.605 0.210 108.675 ;
    END
  END w0_wd_in[7]
  PIN w0_wd_in[8]
    DIRECTION INPUT ;
    USE SIGNAL ;
    SHAPE ABUTMENT ;
    PORT
      LAYER metal3 ;
      RECT 0.000 110.565 0.210 110.635 ;
    END
  END w0_wd_in[8]
  PIN w0_wd_in[9]
    DIRECTION INPUT ;
    USE SIGNAL ;
    SHAPE ABUTMENT ;
    PORT
      LAYER metal3 ;
      RECT 0.000 112.525 0.210 112.595 ;
    END
  END w0_wd_in[9]
  PIN w0_wd_in[10]
    DIRECTION INPUT ;
    USE SIGNAL ;
    SHAPE ABUTMENT ;
    PORT
      LAYER metal3 ;
      RECT 0.000 114.485 0.210 114.555 ;
    END
  END w0_wd_in[10]
  PIN w0_wd_in[11]
    DIRECTION INPUT ;
    USE SIGNAL ;
    SHAPE ABUTMENT ;
    PORT
      LAYER metal3 ;
      RECT 0.000 116.445 0.210 116.515 ;
    END
  END w0_wd_in[11]
  PIN w0_wd_in[12]
    DIRECTION INPUT ;
    USE SIGNAL ;
    SHAPE ABUTMENT ;
    PORT
      LAYER metal3 ;
      RECT 0.000 118.405 0.210 118.475 ;
    END
  END w0_wd_in[12]
  PIN w0_wd_in[13]
    DIRECTION INPUT ;
    USE SIGNAL ;
    SHAPE ABUTMENT ;
    PORT
      LAYER metal3 ;
      RECT 0.000 120.365 0.210 120.435 ;
    END
  END w0_wd_in[13]
  PIN w0_wd_in[14]
    DIRECTION INPUT ;
    USE SIGNAL ;
    SHAPE ABUTMENT ;
    PORT
      LAYER metal3 ;
      RECT 0.000 122.325 0.210 122.395 ;
    END
  END w0_wd_in[14]
  PIN w0_wd_in[15]
    DIRECTION INPUT ;
    USE SIGNAL ;
    SHAPE ABUTMENT ;
    PORT
      LAYER metal3 ;
      RECT 0.000 124.285 0.210 124.355 ;
    END
  END w0_wd_in[15]
  PIN w0_wd_in[16]
    DIRECTION INPUT ;
    USE SIGNAL ;
    SHAPE ABUTMENT ;
    PORT
      LAYER metal3 ;
      RECT 0.000 126.245 0.210 126.315 ;
    END
  END w0_wd_in[16]
  PIN w0_wd_in[17]
    DIRECTION INPUT ;
    USE SIGNAL ;
    SHAPE ABUTMENT ;
    PORT
      LAYER metal3 ;
      RECT 0.000 128.205 0.210 128.275 ;
    END
  END w0_wd_in[17]
  PIN w0_wd_in[18]
    DIRECTION INPUT ;
    USE SIGNAL ;
    SHAPE ABUTMENT ;
    PORT
      LAYER metal3 ;
      RECT 0.000 130.165 0.210 130.235 ;
    END
  END w0_wd_in[18]
  PIN w0_wd_in[19]
    DIRECTION INPUT ;
    USE SIGNAL ;
    SHAPE ABUTMENT ;
    PORT
      LAYER metal3 ;
      RECT 0.000 132.125 0.210 132.195 ;
    END
  END w0_wd_in[19]
  PIN w0_wd_in[20]
    DIRECTION INPUT ;
    USE SIGNAL ;
    SHAPE ABUTMENT ;
    PORT
      LAYER metal3 ;
      RECT 0.000 134.085 0.210 134.155 ;
    END
  END w0_wd_in[20]
  PIN w0_wd_in[21]
    DIRECTION INPUT ;
    USE SIGNAL ;
    SHAPE ABUTMENT ;
    PORT
      LAYER metal3 ;
      RECT 0.000 136.045 0.210 136.115 ;
    END
  END w0_wd_in[21]
  PIN w0_wd_in[22]
    DIRECTION INPUT ;
    USE SIGNAL ;
    SHAPE ABUTMENT ;
    PORT
      LAYER metal3 ;
      RECT 0.000 138.005 0.210 138.075 ;
    END
  END w0_wd_in[22]
  PIN w0_wd_in[23]
    DIRECTION INPUT ;
    USE SIGNAL ;
    SHAPE ABUTMENT ;
    PORT
      LAYER metal3 ;
      RECT 0.000 139.965 0.210 140.035 ;
    END
  END w0_wd_in[23]
  PIN w0_wd_in[24]
    DIRECTION INPUT ;
    USE SIGNAL ;
    SHAPE ABUTMENT ;
    PORT
      LAYER metal3 ;
      RECT 0.000 141.925 0.210 141.995 ;
    END
  END w0_wd_in[24]
  PIN w0_wd_in[25]
    DIRECTION INPUT ;
    USE SIGNAL ;
    SHAPE ABUTMENT ;
    PORT
      LAYER metal3 ;
      RECT 0.000 143.885 0.210 143.955 ;
    END
  END w0_wd_in[25]
  PIN w0_wd_in[26]
    DIRECTION INPUT ;
    USE SIGNAL ;
    SHAPE ABUTMENT ;
    PORT
      LAYER metal3 ;
      RECT 0.000 145.845 0.210 145.915 ;
    END
  END w0_wd_in[26]
  PIN w0_wd_in[27]
    DIRECTION INPUT ;
    USE SIGNAL ;
    SHAPE ABUTMENT ;
    PORT
      LAYER metal3 ;
      RECT 0.000 147.805 0.210 147.875 ;
    END
  END w0_wd_in[27]
  PIN w0_wd_in[28]
    DIRECTION INPUT ;
    USE SIGNAL ;
    SHAPE ABUTMENT ;
    PORT
      LAYER metal3 ;
      RECT 0.000 149.765 0.210 149.835 ;
    END
  END w0_wd_in[28]
  PIN w0_wd_in[29]
    DIRECTION INPUT ;
    USE SIGNAL ;
    SHAPE ABUTMENT ;
    PORT
      LAYER metal3 ;
      RECT 0.000 151.725 0.210 151.795 ;
    END
  END w0_wd_in[29]
  PIN w0_wd_in[30]
    DIRECTION INPUT ;
    USE SIGNAL ;
    SHAPE ABUTMENT ;
    PORT
      LAYER metal3 ;
      RECT 0.000 153.685 0.210 153.755 ;
    END
  END w0_wd_in[30]
  PIN w0_wd_in[31]
    DIRECTION INPUT ;
    USE SIGNAL ;
    SHAPE ABUTMENT ;
    PORT
      LAYER metal3 ;
      RECT 0.000 155.645 0.210 155.715 ;
    END
  END w0_wd_in[31]
  PIN w0_wd_in[32]
    DIRECTION INPUT ;
    USE SIGNAL ;
    SHAPE ABUTMENT ;
    PORT
      LAYER metal3 ;
      RECT 0.000 157.605 0.210 157.675 ;
    END
  END w0_wd_in[32]
  PIN w0_wd_in[33]
    DIRECTION INPUT ;
    USE SIGNAL ;
    SHAPE ABUTMENT ;
    PORT
      LAYER metal3 ;
      RECT 0.000 159.565 0.210 159.635 ;
    END
  END w0_wd_in[33]
  PIN w0_wd_in[34]
    DIRECTION INPUT ;
    USE SIGNAL ;
    SHAPE ABUTMENT ;
    PORT
      LAYER metal3 ;
      RECT 0.000 161.525 0.210 161.595 ;
    END
  END w0_wd_in[34]
  PIN w0_wd_in[35]
    DIRECTION INPUT ;
    USE SIGNAL ;
    SHAPE ABUTMENT ;
    PORT
      LAYER metal3 ;
      RECT 0.000 163.485 0.210 163.555 ;
    END
  END w0_wd_in[35]
  PIN w0_wd_in[36]
    DIRECTION INPUT ;
    USE SIGNAL ;
    SHAPE ABUTMENT ;
    PORT
      LAYER metal3 ;
      RECT 0.000 165.445 0.210 165.515 ;
    END
  END w0_wd_in[36]
  PIN w0_wd_in[37]
    DIRECTION INPUT ;
    USE SIGNAL ;
    SHAPE ABUTMENT ;
    PORT
      LAYER metal3 ;
      RECT 0.000 167.405 0.210 167.475 ;
    END
  END w0_wd_in[37]
  PIN w0_wd_in[38]
    DIRECTION INPUT ;
    USE SIGNAL ;
    SHAPE ABUTMENT ;
    PORT
      LAYER metal3 ;
      RECT 0.000 169.365 0.210 169.435 ;
    END
  END w0_wd_in[38]
  PIN w0_wd_in[39]
    DIRECTION INPUT ;
    USE SIGNAL ;
    SHAPE ABUTMENT ;
    PORT
      LAYER metal3 ;
      RECT 0.000 171.325 0.210 171.395 ;
    END
  END w0_wd_in[39]
  PIN w0_wd_in[40]
    DIRECTION INPUT ;
    USE SIGNAL ;
    SHAPE ABUTMENT ;
    PORT
      LAYER metal3 ;
      RECT 0.000 173.285 0.210 173.355 ;
    END
  END w0_wd_in[40]
  PIN w0_wd_in[41]
    DIRECTION INPUT ;
    USE SIGNAL ;
    SHAPE ABUTMENT ;
    PORT
      LAYER metal3 ;
      RECT 0.000 175.245 0.210 175.315 ;
    END
  END w0_wd_in[41]
  PIN w0_wd_in[42]
    DIRECTION INPUT ;
    USE SIGNAL ;
    SHAPE ABUTMENT ;
    PORT
      LAYER metal3 ;
      RECT 0.000 177.205 0.210 177.275 ;
    END
  END w0_wd_in[42]
  PIN w0_wd_in[43]
    DIRECTION INPUT ;
    USE SIGNAL ;
    SHAPE ABUTMENT ;
    PORT
      LAYER metal3 ;
      RECT 0.000 179.165 0.210 179.235 ;
    END
  END w0_wd_in[43]
  PIN w0_wd_in[44]
    DIRECTION INPUT ;
    USE SIGNAL ;
    SHAPE ABUTMENT ;
    PORT
      LAYER metal3 ;
      RECT 0.000 181.125 0.210 181.195 ;
    END
  END w0_wd_in[44]
  PIN w0_wd_in[45]
    DIRECTION INPUT ;
    USE SIGNAL ;
    SHAPE ABUTMENT ;
    PORT
      LAYER metal3 ;
      RECT 0.000 183.085 0.210 183.155 ;
    END
  END w0_wd_in[45]
  PIN w0_wd_in[46]
    DIRECTION INPUT ;
    USE SIGNAL ;
    SHAPE ABUTMENT ;
    PORT
      LAYER metal3 ;
      RECT 0.000 185.045 0.210 185.115 ;
    END
  END w0_wd_in[46]
  PIN w0_wd_in[47]
    DIRECTION INPUT ;
    USE SIGNAL ;
    SHAPE ABUTMENT ;
    PORT
      LAYER metal3 ;
      RECT 0.000 187.005 0.210 187.075 ;
    END
  END w0_wd_in[47]
  PIN w0_wd_in[48]
    DIRECTION INPUT ;
    USE SIGNAL ;
    SHAPE ABUTMENT ;
    PORT
      LAYER metal3 ;
      RECT 119.490 94.885 119.700 94.955 ;
    END
  END w0_wd_in[48]
  PIN w0_wd_in[49]
    DIRECTION INPUT ;
    USE SIGNAL ;
    SHAPE ABUTMENT ;
    PORT
      LAYER metal3 ;
      RECT 119.490 96.845 119.700 96.915 ;
    END
  END w0_wd_in[49]
  PIN w0_wd_in[50]
    DIRECTION INPUT ;
    USE SIGNAL ;
    SHAPE ABUTMENT ;
    PORT
      LAYER metal3 ;
      RECT 119.490 98.805 119.700 98.875 ;
    END
  END w0_wd_in[50]
  PIN w0_wd_in[51]
    DIRECTION INPUT ;
    USE SIGNAL ;
    SHAPE ABUTMENT ;
    PORT
      LAYER metal3 ;
      RECT 119.490 100.765 119.700 100.835 ;
    END
  END w0_wd_in[51]
  PIN w0_wd_in[52]
    DIRECTION INPUT ;
    USE SIGNAL ;
    SHAPE ABUTMENT ;
    PORT
      LAYER metal3 ;
      RECT 119.490 102.725 119.700 102.795 ;
    END
  END w0_wd_in[52]
  PIN w0_wd_in[53]
    DIRECTION INPUT ;
    USE SIGNAL ;
    SHAPE ABUTMENT ;
    PORT
      LAYER metal3 ;
      RECT 119.490 104.685 119.700 104.755 ;
    END
  END w0_wd_in[53]
  PIN w0_wd_in[54]
    DIRECTION INPUT ;
    USE SIGNAL ;
    SHAPE ABUTMENT ;
    PORT
      LAYER metal3 ;
      RECT 119.490 106.645 119.700 106.715 ;
    END
  END w0_wd_in[54]
  PIN w0_wd_in[55]
    DIRECTION INPUT ;
    USE SIGNAL ;
    SHAPE ABUTMENT ;
    PORT
      LAYER metal3 ;
      RECT 119.490 108.605 119.700 108.675 ;
    END
  END w0_wd_in[55]
  PIN w0_wd_in[56]
    DIRECTION INPUT ;
    USE SIGNAL ;
    SHAPE ABUTMENT ;
    PORT
      LAYER metal3 ;
      RECT 119.490 110.565 119.700 110.635 ;
    END
  END w0_wd_in[56]
  PIN w0_wd_in[57]
    DIRECTION INPUT ;
    USE SIGNAL ;
    SHAPE ABUTMENT ;
    PORT
      LAYER metal3 ;
      RECT 119.490 112.525 119.700 112.595 ;
    END
  END w0_wd_in[57]
  PIN w0_wd_in[58]
    DIRECTION INPUT ;
    USE SIGNAL ;
    SHAPE ABUTMENT ;
    PORT
      LAYER metal3 ;
      RECT 119.490 114.485 119.700 114.555 ;
    END
  END w0_wd_in[58]
  PIN w0_wd_in[59]
    DIRECTION INPUT ;
    USE SIGNAL ;
    SHAPE ABUTMENT ;
    PORT
      LAYER metal3 ;
      RECT 119.490 116.445 119.700 116.515 ;
    END
  END w0_wd_in[59]
  PIN w0_wd_in[60]
    DIRECTION INPUT ;
    USE SIGNAL ;
    SHAPE ABUTMENT ;
    PORT
      LAYER metal3 ;
      RECT 119.490 118.405 119.700 118.475 ;
    END
  END w0_wd_in[60]
  PIN w0_wd_in[61]
    DIRECTION INPUT ;
    USE SIGNAL ;
    SHAPE ABUTMENT ;
    PORT
      LAYER metal3 ;
      RECT 119.490 120.365 119.700 120.435 ;
    END
  END w0_wd_in[61]
  PIN w0_wd_in[62]
    DIRECTION INPUT ;
    USE SIGNAL ;
    SHAPE ABUTMENT ;
    PORT
      LAYER metal3 ;
      RECT 119.490 122.325 119.700 122.395 ;
    END
  END w0_wd_in[62]
  PIN w0_wd_in[63]
    DIRECTION INPUT ;
    USE SIGNAL ;
    SHAPE ABUTMENT ;
    PORT
      LAYER metal3 ;
      RECT 119.490 124.285 119.700 124.355 ;
    END
  END w0_wd_in[63]
  PIN w0_wd_in[64]
    DIRECTION INPUT ;
    USE SIGNAL ;
    SHAPE ABUTMENT ;
    PORT
      LAYER metal3 ;
      RECT 119.490 126.245 119.700 126.315 ;
    END
  END w0_wd_in[64]
  PIN w0_wd_in[65]
    DIRECTION INPUT ;
    USE SIGNAL ;
    SHAPE ABUTMENT ;
    PORT
      LAYER metal3 ;
      RECT 119.490 128.205 119.700 128.275 ;
    END
  END w0_wd_in[65]
  PIN w0_wd_in[66]
    DIRECTION INPUT ;
    USE SIGNAL ;
    SHAPE ABUTMENT ;
    PORT
      LAYER metal3 ;
      RECT 119.490 130.165 119.700 130.235 ;
    END
  END w0_wd_in[66]
  PIN w0_wd_in[67]
    DIRECTION INPUT ;
    USE SIGNAL ;
    SHAPE ABUTMENT ;
    PORT
      LAYER metal3 ;
      RECT 119.490 132.125 119.700 132.195 ;
    END
  END w0_wd_in[67]
  PIN w0_wd_in[68]
    DIRECTION INPUT ;
    USE SIGNAL ;
    SHAPE ABUTMENT ;
    PORT
      LAYER metal3 ;
      RECT 119.490 134.085 119.700 134.155 ;
    END
  END w0_wd_in[68]
  PIN w0_wd_in[69]
    DIRECTION INPUT ;
    USE SIGNAL ;
    SHAPE ABUTMENT ;
    PORT
      LAYER metal3 ;
      RECT 119.490 136.045 119.700 136.115 ;
    END
  END w0_wd_in[69]
  PIN w0_wd_in[70]
    DIRECTION INPUT ;
    USE SIGNAL ;
    SHAPE ABUTMENT ;
    PORT
      LAYER metal3 ;
      RECT 119.490 138.005 119.700 138.075 ;
    END
  END w0_wd_in[70]
  PIN w0_wd_in[71]
    DIRECTION INPUT ;
    USE SIGNAL ;
    SHAPE ABUTMENT ;
    PORT
      LAYER metal3 ;
      RECT 119.490 139.965 119.700 140.035 ;
    END
  END w0_wd_in[71]
  PIN w0_wd_in[72]
    DIRECTION INPUT ;
    USE SIGNAL ;
    SHAPE ABUTMENT ;
    PORT
      LAYER metal3 ;
      RECT 119.490 141.925 119.700 141.995 ;
    END
  END w0_wd_in[72]
  PIN w0_wd_in[73]
    DIRECTION INPUT ;
    USE SIGNAL ;
    SHAPE ABUTMENT ;
    PORT
      LAYER metal3 ;
      RECT 119.490 143.885 119.700 143.955 ;
    END
  END w0_wd_in[73]
  PIN w0_wd_in[74]
    DIRECTION INPUT ;
    USE SIGNAL ;
    SHAPE ABUTMENT ;
    PORT
      LAYER metal3 ;
      RECT 119.490 145.845 119.700 145.915 ;
    END
  END w0_wd_in[74]
  PIN w0_wd_in[75]
    DIRECTION INPUT ;
    USE SIGNAL ;
    SHAPE ABUTMENT ;
    PORT
      LAYER metal3 ;
      RECT 119.490 147.805 119.700 147.875 ;
    END
  END w0_wd_in[75]
  PIN w0_wd_in[76]
    DIRECTION INPUT ;
    USE SIGNAL ;
    SHAPE ABUTMENT ;
    PORT
      LAYER metal3 ;
      RECT 119.490 149.765 119.700 149.835 ;
    END
  END w0_wd_in[76]
  PIN w0_wd_in[77]
    DIRECTION INPUT ;
    USE SIGNAL ;
    SHAPE ABUTMENT ;
    PORT
      LAYER metal3 ;
      RECT 119.490 151.725 119.700 151.795 ;
    END
  END w0_wd_in[77]
  PIN w0_wd_in[78]
    DIRECTION INPUT ;
    USE SIGNAL ;
    SHAPE ABUTMENT ;
    PORT
      LAYER metal3 ;
      RECT 119.490 153.685 119.700 153.755 ;
    END
  END w0_wd_in[78]
  PIN w0_wd_in[79]
    DIRECTION INPUT ;
    USE SIGNAL ;
    SHAPE ABUTMENT ;
    PORT
      LAYER metal3 ;
      RECT 119.490 155.645 119.700 155.715 ;
    END
  END w0_wd_in[79]
  PIN w0_wd_in[80]
    DIRECTION INPUT ;
    USE SIGNAL ;
    SHAPE ABUTMENT ;
    PORT
      LAYER metal3 ;
      RECT 119.490 157.605 119.700 157.675 ;
    END
  END w0_wd_in[80]
  PIN w0_wd_in[81]
    DIRECTION INPUT ;
    USE SIGNAL ;
    SHAPE ABUTMENT ;
    PORT
      LAYER metal3 ;
      RECT 119.490 159.565 119.700 159.635 ;
    END
  END w0_wd_in[81]
  PIN w0_wd_in[82]
    DIRECTION INPUT ;
    USE SIGNAL ;
    SHAPE ABUTMENT ;
    PORT
      LAYER metal3 ;
      RECT 119.490 161.525 119.700 161.595 ;
    END
  END w0_wd_in[82]
  PIN w0_wd_in[83]
    DIRECTION INPUT ;
    USE SIGNAL ;
    SHAPE ABUTMENT ;
    PORT
      LAYER metal3 ;
      RECT 119.490 163.485 119.700 163.555 ;
    END
  END w0_wd_in[83]
  PIN w0_wd_in[84]
    DIRECTION INPUT ;
    USE SIGNAL ;
    SHAPE ABUTMENT ;
    PORT
      LAYER metal3 ;
      RECT 119.490 165.445 119.700 165.515 ;
    END
  END w0_wd_in[84]
  PIN w0_wd_in[85]
    DIRECTION INPUT ;
    USE SIGNAL ;
    SHAPE ABUTMENT ;
    PORT
      LAYER metal3 ;
      RECT 119.490 167.405 119.700 167.475 ;
    END
  END w0_wd_in[85]
  PIN w0_wd_in[86]
    DIRECTION INPUT ;
    USE SIGNAL ;
    SHAPE ABUTMENT ;
    PORT
      LAYER metal3 ;
      RECT 119.490 169.365 119.700 169.435 ;
    END
  END w0_wd_in[86]
  PIN w0_wd_in[87]
    DIRECTION INPUT ;
    USE SIGNAL ;
    SHAPE ABUTMENT ;
    PORT
      LAYER metal3 ;
      RECT 119.490 171.325 119.700 171.395 ;
    END
  END w0_wd_in[87]
  PIN w0_wd_in[88]
    DIRECTION INPUT ;
    USE SIGNAL ;
    SHAPE ABUTMENT ;
    PORT
      LAYER metal3 ;
      RECT 119.490 173.285 119.700 173.355 ;
    END
  END w0_wd_in[88]
  PIN w0_wd_in[89]
    DIRECTION INPUT ;
    USE SIGNAL ;
    SHAPE ABUTMENT ;
    PORT
      LAYER metal3 ;
      RECT 119.490 175.245 119.700 175.315 ;
    END
  END w0_wd_in[89]
  PIN w0_wd_in[90]
    DIRECTION INPUT ;
    USE SIGNAL ;
    SHAPE ABUTMENT ;
    PORT
      LAYER metal3 ;
      RECT 119.490 177.205 119.700 177.275 ;
    END
  END w0_wd_in[90]
  PIN w0_wd_in[91]
    DIRECTION INPUT ;
    USE SIGNAL ;
    SHAPE ABUTMENT ;
    PORT
      LAYER metal3 ;
      RECT 119.490 179.165 119.700 179.235 ;
    END
  END w0_wd_in[91]
  PIN w0_wd_in[92]
    DIRECTION INPUT ;
    USE SIGNAL ;
    SHAPE ABUTMENT ;
    PORT
      LAYER metal3 ;
      RECT 119.490 181.125 119.700 181.195 ;
    END
  END w0_wd_in[92]
  PIN w0_wd_in[93]
    DIRECTION INPUT ;
    USE SIGNAL ;
    SHAPE ABUTMENT ;
    PORT
      LAYER metal3 ;
      RECT 119.490 183.085 119.700 183.155 ;
    END
  END w0_wd_in[93]
  PIN w0_wd_in[94]
    DIRECTION INPUT ;
    USE SIGNAL ;
    SHAPE ABUTMENT ;
    PORT
      LAYER metal3 ;
      RECT 119.490 185.045 119.700 185.115 ;
    END
  END w0_wd_in[94]
  PIN w0_wd_in[95]
    DIRECTION INPUT ;
    USE SIGNAL ;
    SHAPE ABUTMENT ;
    PORT
      LAYER metal3 ;
      RECT 119.490 187.005 119.700 187.075 ;
    END
  END w0_wd_in[95]
  PIN w0_wd_in[96]
    DIRECTION OUTPUT ;
    USE SIGNAL ;
    SHAPE ABUTMENT ;
    PORT
      LAYER metal2 ;
      RECT 1.105 0.000 1.175 0.210 ;
    END
  END w0_wd_in[96]
  PIN w0_wd_in[97]
    DIRECTION OUTPUT ;
    USE SIGNAL ;
    SHAPE ABUTMENT ;
    PORT
      LAYER metal2 ;
      RECT 1.675 0.000 1.745 0.210 ;
    END
  END w0_wd_in[97]
  PIN w0_wd_in[98]
    DIRECTION OUTPUT ;
    USE SIGNAL ;
    SHAPE ABUTMENT ;
    PORT
      LAYER metal2 ;
      RECT 2.245 0.000 2.315 0.210 ;
    END
  END w0_wd_in[98]
  PIN w0_wd_in[99]
    DIRECTION OUTPUT ;
    USE SIGNAL ;
    SHAPE ABUTMENT ;
    PORT
      LAYER metal2 ;
      RECT 2.815 0.000 2.885 0.210 ;
    END
  END w0_wd_in[99]
  PIN w0_wd_in[100]
    DIRECTION OUTPUT ;
    USE SIGNAL ;
    SHAPE ABUTMENT ;
    PORT
      LAYER metal2 ;
      RECT 3.385 0.000 3.455 0.210 ;
    END
  END w0_wd_in[100]
  PIN w0_wd_in[101]
    DIRECTION OUTPUT ;
    USE SIGNAL ;
    SHAPE ABUTMENT ;
    PORT
      LAYER metal2 ;
      RECT 3.955 0.000 4.025 0.210 ;
    END
  END w0_wd_in[101]
  PIN w0_wd_in[102]
    DIRECTION OUTPUT ;
    USE SIGNAL ;
    SHAPE ABUTMENT ;
    PORT
      LAYER metal2 ;
      RECT 4.525 0.000 4.595 0.210 ;
    END
  END w0_wd_in[102]
  PIN w0_wd_in[103]
    DIRECTION OUTPUT ;
    USE SIGNAL ;
    SHAPE ABUTMENT ;
    PORT
      LAYER metal2 ;
      RECT 5.095 0.000 5.165 0.210 ;
    END
  END w0_wd_in[103]
  PIN w0_wd_in[104]
    DIRECTION OUTPUT ;
    USE SIGNAL ;
    SHAPE ABUTMENT ;
    PORT
      LAYER metal2 ;
      RECT 5.665 0.000 5.735 0.210 ;
    END
  END w0_wd_in[104]
  PIN w0_wd_in[105]
    DIRECTION OUTPUT ;
    USE SIGNAL ;
    SHAPE ABUTMENT ;
    PORT
      LAYER metal2 ;
      RECT 6.235 0.000 6.305 0.210 ;
    END
  END w0_wd_in[105]
  PIN w0_wd_in[106]
    DIRECTION OUTPUT ;
    USE SIGNAL ;
    SHAPE ABUTMENT ;
    PORT
      LAYER metal2 ;
      RECT 6.805 0.000 6.875 0.210 ;
    END
  END w0_wd_in[106]
  PIN w0_wd_in[107]
    DIRECTION OUTPUT ;
    USE SIGNAL ;
    SHAPE ABUTMENT ;
    PORT
      LAYER metal2 ;
      RECT 7.375 0.000 7.445 0.210 ;
    END
  END w0_wd_in[107]
  PIN w0_wd_in[108]
    DIRECTION OUTPUT ;
    USE SIGNAL ;
    SHAPE ABUTMENT ;
    PORT
      LAYER metal2 ;
      RECT 7.945 0.000 8.015 0.210 ;
    END
  END w0_wd_in[108]
  PIN w0_wd_in[109]
    DIRECTION OUTPUT ;
    USE SIGNAL ;
    SHAPE ABUTMENT ;
    PORT
      LAYER metal2 ;
      RECT 8.515 0.000 8.585 0.210 ;
    END
  END w0_wd_in[109]
  PIN w0_wd_in[110]
    DIRECTION OUTPUT ;
    USE SIGNAL ;
    SHAPE ABUTMENT ;
    PORT
      LAYER metal2 ;
      RECT 9.085 0.000 9.155 0.210 ;
    END
  END w0_wd_in[110]
  PIN w0_wd_in[111]
    DIRECTION OUTPUT ;
    USE SIGNAL ;
    SHAPE ABUTMENT ;
    PORT
      LAYER metal2 ;
      RECT 9.655 0.000 9.725 0.210 ;
    END
  END w0_wd_in[111]
  PIN w0_wd_in[112]
    DIRECTION OUTPUT ;
    USE SIGNAL ;
    SHAPE ABUTMENT ;
    PORT
      LAYER metal2 ;
      RECT 10.225 0.000 10.295 0.210 ;
    END
  END w0_wd_in[112]
  PIN w0_wd_in[113]
    DIRECTION OUTPUT ;
    USE SIGNAL ;
    SHAPE ABUTMENT ;
    PORT
      LAYER metal2 ;
      RECT 10.795 0.000 10.865 0.210 ;
    END
  END w0_wd_in[113]
  PIN w0_wd_in[114]
    DIRECTION OUTPUT ;
    USE SIGNAL ;
    SHAPE ABUTMENT ;
    PORT
      LAYER metal2 ;
      RECT 11.365 0.000 11.435 0.210 ;
    END
  END w0_wd_in[114]
  PIN w0_wd_in[115]
    DIRECTION OUTPUT ;
    USE SIGNAL ;
    SHAPE ABUTMENT ;
    PORT
      LAYER metal2 ;
      RECT 11.935 0.000 12.005 0.210 ;
    END
  END w0_wd_in[115]
  PIN w0_wd_in[116]
    DIRECTION OUTPUT ;
    USE SIGNAL ;
    SHAPE ABUTMENT ;
    PORT
      LAYER metal2 ;
      RECT 12.505 0.000 12.575 0.210 ;
    END
  END w0_wd_in[116]
  PIN w0_wd_in[117]
    DIRECTION OUTPUT ;
    USE SIGNAL ;
    SHAPE ABUTMENT ;
    PORT
      LAYER metal2 ;
      RECT 13.075 0.000 13.145 0.210 ;
    END
  END w0_wd_in[117]
  PIN w0_wd_in[118]
    DIRECTION OUTPUT ;
    USE SIGNAL ;
    SHAPE ABUTMENT ;
    PORT
      LAYER metal2 ;
      RECT 13.645 0.000 13.715 0.210 ;
    END
  END w0_wd_in[118]
  PIN w0_wd_in[119]
    DIRECTION OUTPUT ;
    USE SIGNAL ;
    SHAPE ABUTMENT ;
    PORT
      LAYER metal2 ;
      RECT 14.215 0.000 14.285 0.210 ;
    END
  END w0_wd_in[119]
  PIN w0_wd_in[120]
    DIRECTION OUTPUT ;
    USE SIGNAL ;
    SHAPE ABUTMENT ;
    PORT
      LAYER metal2 ;
      RECT 14.785 0.000 14.855 0.210 ;
    END
  END w0_wd_in[120]
  PIN w0_wd_in[121]
    DIRECTION OUTPUT ;
    USE SIGNAL ;
    SHAPE ABUTMENT ;
    PORT
      LAYER metal2 ;
      RECT 15.355 0.000 15.425 0.210 ;
    END
  END w0_wd_in[121]
  PIN w0_wd_in[122]
    DIRECTION OUTPUT ;
    USE SIGNAL ;
    SHAPE ABUTMENT ;
    PORT
      LAYER metal2 ;
      RECT 15.925 0.000 15.995 0.210 ;
    END
  END w0_wd_in[122]
  PIN w0_wd_in[123]
    DIRECTION OUTPUT ;
    USE SIGNAL ;
    SHAPE ABUTMENT ;
    PORT
      LAYER metal2 ;
      RECT 16.495 0.000 16.565 0.210 ;
    END
  END w0_wd_in[123]
  PIN w0_wd_in[124]
    DIRECTION OUTPUT ;
    USE SIGNAL ;
    SHAPE ABUTMENT ;
    PORT
      LAYER metal2 ;
      RECT 17.065 0.000 17.135 0.210 ;
    END
  END w0_wd_in[124]
  PIN w0_wd_in[125]
    DIRECTION OUTPUT ;
    USE SIGNAL ;
    SHAPE ABUTMENT ;
    PORT
      LAYER metal2 ;
      RECT 17.635 0.000 17.705 0.210 ;
    END
  END w0_wd_in[125]
  PIN w0_wd_in[126]
    DIRECTION OUTPUT ;
    USE SIGNAL ;
    SHAPE ABUTMENT ;
    PORT
      LAYER metal2 ;
      RECT 18.205 0.000 18.275 0.210 ;
    END
  END w0_wd_in[126]
  PIN w0_wd_in[127]
    DIRECTION OUTPUT ;
    USE SIGNAL ;
    SHAPE ABUTMENT ;
    PORT
      LAYER metal2 ;
      RECT 18.775 0.000 18.845 0.210 ;
    END
  END w0_wd_in[127]
  PIN w0_wd_in[128]
    DIRECTION OUTPUT ;
    USE SIGNAL ;
    SHAPE ABUTMENT ;
    PORT
      LAYER metal2 ;
      RECT 19.345 0.000 19.415 0.210 ;
    END
  END w0_wd_in[128]
  PIN w0_wd_in[129]
    DIRECTION OUTPUT ;
    USE SIGNAL ;
    SHAPE ABUTMENT ;
    PORT
      LAYER metal2 ;
      RECT 19.915 0.000 19.985 0.210 ;
    END
  END w0_wd_in[129]
  PIN w0_wd_in[130]
    DIRECTION OUTPUT ;
    USE SIGNAL ;
    SHAPE ABUTMENT ;
    PORT
      LAYER metal2 ;
      RECT 20.485 0.000 20.555 0.210 ;
    END
  END w0_wd_in[130]
  PIN w0_wd_in[131]
    DIRECTION OUTPUT ;
    USE SIGNAL ;
    SHAPE ABUTMENT ;
    PORT
      LAYER metal2 ;
      RECT 21.055 0.000 21.125 0.210 ;
    END
  END w0_wd_in[131]
  PIN w0_wd_in[132]
    DIRECTION OUTPUT ;
    USE SIGNAL ;
    SHAPE ABUTMENT ;
    PORT
      LAYER metal2 ;
      RECT 21.625 0.000 21.695 0.210 ;
    END
  END w0_wd_in[132]
  PIN w0_wd_in[133]
    DIRECTION OUTPUT ;
    USE SIGNAL ;
    SHAPE ABUTMENT ;
    PORT
      LAYER metal2 ;
      RECT 22.195 0.000 22.265 0.210 ;
    END
  END w0_wd_in[133]
  PIN w0_wd_in[134]
    DIRECTION OUTPUT ;
    USE SIGNAL ;
    SHAPE ABUTMENT ;
    PORT
      LAYER metal2 ;
      RECT 22.765 0.000 22.835 0.210 ;
    END
  END w0_wd_in[134]
  PIN w0_wd_in[135]
    DIRECTION OUTPUT ;
    USE SIGNAL ;
    SHAPE ABUTMENT ;
    PORT
      LAYER metal2 ;
      RECT 23.335 0.000 23.405 0.210 ;
    END
  END w0_wd_in[135]
  PIN w0_wd_in[136]
    DIRECTION OUTPUT ;
    USE SIGNAL ;
    SHAPE ABUTMENT ;
    PORT
      LAYER metal2 ;
      RECT 23.905 0.000 23.975 0.210 ;
    END
  END w0_wd_in[136]
  PIN w0_wd_in[137]
    DIRECTION OUTPUT ;
    USE SIGNAL ;
    SHAPE ABUTMENT ;
    PORT
      LAYER metal2 ;
      RECT 24.475 0.000 24.545 0.210 ;
    END
  END w0_wd_in[137]
  PIN w0_wd_in[138]
    DIRECTION OUTPUT ;
    USE SIGNAL ;
    SHAPE ABUTMENT ;
    PORT
      LAYER metal2 ;
      RECT 25.045 0.000 25.115 0.210 ;
    END
  END w0_wd_in[138]
  PIN w0_wd_in[139]
    DIRECTION OUTPUT ;
    USE SIGNAL ;
    SHAPE ABUTMENT ;
    PORT
      LAYER metal2 ;
      RECT 25.615 0.000 25.685 0.210 ;
    END
  END w0_wd_in[139]
  PIN w0_wd_in[140]
    DIRECTION OUTPUT ;
    USE SIGNAL ;
    SHAPE ABUTMENT ;
    PORT
      LAYER metal2 ;
      RECT 26.185 0.000 26.255 0.210 ;
    END
  END w0_wd_in[140]
  PIN w0_wd_in[141]
    DIRECTION OUTPUT ;
    USE SIGNAL ;
    SHAPE ABUTMENT ;
    PORT
      LAYER metal2 ;
      RECT 26.755 0.000 26.825 0.210 ;
    END
  END w0_wd_in[141]
  PIN w0_wd_in[142]
    DIRECTION OUTPUT ;
    USE SIGNAL ;
    SHAPE ABUTMENT ;
    PORT
      LAYER metal2 ;
      RECT 27.325 0.000 27.395 0.210 ;
    END
  END w0_wd_in[142]
  PIN w0_wd_in[143]
    DIRECTION OUTPUT ;
    USE SIGNAL ;
    SHAPE ABUTMENT ;
    PORT
      LAYER metal2 ;
      RECT 27.895 0.000 27.965 0.210 ;
    END
  END w0_wd_in[143]
  PIN w0_wd_in[144]
    DIRECTION OUTPUT ;
    USE SIGNAL ;
    SHAPE ABUTMENT ;
    PORT
      LAYER metal2 ;
      RECT 28.465 0.000 28.535 0.210 ;
    END
  END w0_wd_in[144]
  PIN w0_wd_in[145]
    DIRECTION OUTPUT ;
    USE SIGNAL ;
    SHAPE ABUTMENT ;
    PORT
      LAYER metal2 ;
      RECT 29.035 0.000 29.105 0.210 ;
    END
  END w0_wd_in[145]
  PIN w0_wd_in[146]
    DIRECTION OUTPUT ;
    USE SIGNAL ;
    SHAPE ABUTMENT ;
    PORT
      LAYER metal2 ;
      RECT 29.605 0.000 29.675 0.210 ;
    END
  END w0_wd_in[146]
  PIN w0_wd_in[147]
    DIRECTION OUTPUT ;
    USE SIGNAL ;
    SHAPE ABUTMENT ;
    PORT
      LAYER metal2 ;
      RECT 30.175 0.000 30.245 0.210 ;
    END
  END w0_wd_in[147]
  PIN w0_wd_in[148]
    DIRECTION OUTPUT ;
    USE SIGNAL ;
    SHAPE ABUTMENT ;
    PORT
      LAYER metal2 ;
      RECT 30.745 0.000 30.815 0.210 ;
    END
  END w0_wd_in[148]
  PIN w0_wd_in[149]
    DIRECTION OUTPUT ;
    USE SIGNAL ;
    SHAPE ABUTMENT ;
    PORT
      LAYER metal2 ;
      RECT 31.315 0.000 31.385 0.210 ;
    END
  END w0_wd_in[149]
  PIN w0_wd_in[150]
    DIRECTION OUTPUT ;
    USE SIGNAL ;
    SHAPE ABUTMENT ;
    PORT
      LAYER metal2 ;
      RECT 31.885 0.000 31.955 0.210 ;
    END
  END w0_wd_in[150]
  PIN w0_wd_in[151]
    DIRECTION OUTPUT ;
    USE SIGNAL ;
    SHAPE ABUTMENT ;
    PORT
      LAYER metal2 ;
      RECT 32.455 0.000 32.525 0.210 ;
    END
  END w0_wd_in[151]
  PIN w0_wd_in[152]
    DIRECTION OUTPUT ;
    USE SIGNAL ;
    SHAPE ABUTMENT ;
    PORT
      LAYER metal2 ;
      RECT 33.025 0.000 33.095 0.210 ;
    END
  END w0_wd_in[152]
  PIN w0_wd_in[153]
    DIRECTION OUTPUT ;
    USE SIGNAL ;
    SHAPE ABUTMENT ;
    PORT
      LAYER metal2 ;
      RECT 33.595 0.000 33.665 0.210 ;
    END
  END w0_wd_in[153]
  PIN w0_wd_in[154]
    DIRECTION OUTPUT ;
    USE SIGNAL ;
    SHAPE ABUTMENT ;
    PORT
      LAYER metal2 ;
      RECT 34.165 0.000 34.235 0.210 ;
    END
  END w0_wd_in[154]
  PIN w0_wd_in[155]
    DIRECTION OUTPUT ;
    USE SIGNAL ;
    SHAPE ABUTMENT ;
    PORT
      LAYER metal2 ;
      RECT 34.735 0.000 34.805 0.210 ;
    END
  END w0_wd_in[155]
  PIN w0_wd_in[156]
    DIRECTION OUTPUT ;
    USE SIGNAL ;
    SHAPE ABUTMENT ;
    PORT
      LAYER metal2 ;
      RECT 35.305 0.000 35.375 0.210 ;
    END
  END w0_wd_in[156]
  PIN w0_wd_in[157]
    DIRECTION OUTPUT ;
    USE SIGNAL ;
    SHAPE ABUTMENT ;
    PORT
      LAYER metal2 ;
      RECT 35.875 0.000 35.945 0.210 ;
    END
  END w0_wd_in[157]
  PIN w0_wd_in[158]
    DIRECTION OUTPUT ;
    USE SIGNAL ;
    SHAPE ABUTMENT ;
    PORT
      LAYER metal2 ;
      RECT 36.445 0.000 36.515 0.210 ;
    END
  END w0_wd_in[158]
  PIN w0_wd_in[159]
    DIRECTION OUTPUT ;
    USE SIGNAL ;
    SHAPE ABUTMENT ;
    PORT
      LAYER metal2 ;
      RECT 37.015 0.000 37.085 0.210 ;
    END
  END w0_wd_in[159]
  PIN w0_wd_in[160]
    DIRECTION OUTPUT ;
    USE SIGNAL ;
    SHAPE ABUTMENT ;
    PORT
      LAYER metal2 ;
      RECT 37.585 0.000 37.655 0.210 ;
    END
  END w0_wd_in[160]
  PIN w0_wd_in[161]
    DIRECTION OUTPUT ;
    USE SIGNAL ;
    SHAPE ABUTMENT ;
    PORT
      LAYER metal2 ;
      RECT 38.155 0.000 38.225 0.210 ;
    END
  END w0_wd_in[161]
  PIN w0_wd_in[162]
    DIRECTION OUTPUT ;
    USE SIGNAL ;
    SHAPE ABUTMENT ;
    PORT
      LAYER metal2 ;
      RECT 38.725 0.000 38.795 0.210 ;
    END
  END w0_wd_in[162]
  PIN w0_wd_in[163]
    DIRECTION OUTPUT ;
    USE SIGNAL ;
    SHAPE ABUTMENT ;
    PORT
      LAYER metal2 ;
      RECT 39.295 0.000 39.365 0.210 ;
    END
  END w0_wd_in[163]
  PIN w0_wd_in[164]
    DIRECTION OUTPUT ;
    USE SIGNAL ;
    SHAPE ABUTMENT ;
    PORT
      LAYER metal2 ;
      RECT 39.865 0.000 39.935 0.210 ;
    END
  END w0_wd_in[164]
  PIN w0_wd_in[165]
    DIRECTION OUTPUT ;
    USE SIGNAL ;
    SHAPE ABUTMENT ;
    PORT
      LAYER metal2 ;
      RECT 40.435 0.000 40.505 0.210 ;
    END
  END w0_wd_in[165]
  PIN w0_wd_in[166]
    DIRECTION OUTPUT ;
    USE SIGNAL ;
    SHAPE ABUTMENT ;
    PORT
      LAYER metal2 ;
      RECT 41.005 0.000 41.075 0.210 ;
    END
  END w0_wd_in[166]
  PIN w0_wd_in[167]
    DIRECTION OUTPUT ;
    USE SIGNAL ;
    SHAPE ABUTMENT ;
    PORT
      LAYER metal2 ;
      RECT 41.575 0.000 41.645 0.210 ;
    END
  END w0_wd_in[167]
  PIN w0_wd_in[168]
    DIRECTION OUTPUT ;
    USE SIGNAL ;
    SHAPE ABUTMENT ;
    PORT
      LAYER metal2 ;
      RECT 42.145 0.000 42.215 0.210 ;
    END
  END w0_wd_in[168]
  PIN w0_wd_in[169]
    DIRECTION OUTPUT ;
    USE SIGNAL ;
    SHAPE ABUTMENT ;
    PORT
      LAYER metal2 ;
      RECT 42.715 0.000 42.785 0.210 ;
    END
  END w0_wd_in[169]
  PIN w0_wd_in[170]
    DIRECTION OUTPUT ;
    USE SIGNAL ;
    SHAPE ABUTMENT ;
    PORT
      LAYER metal2 ;
      RECT 43.285 0.000 43.355 0.210 ;
    END
  END w0_wd_in[170]
  PIN w0_wd_in[171]
    DIRECTION OUTPUT ;
    USE SIGNAL ;
    SHAPE ABUTMENT ;
    PORT
      LAYER metal2 ;
      RECT 43.855 0.000 43.925 0.210 ;
    END
  END w0_wd_in[171]
  PIN w0_wd_in[172]
    DIRECTION OUTPUT ;
    USE SIGNAL ;
    SHAPE ABUTMENT ;
    PORT
      LAYER metal2 ;
      RECT 44.425 0.000 44.495 0.210 ;
    END
  END w0_wd_in[172]
  PIN w0_wd_in[173]
    DIRECTION OUTPUT ;
    USE SIGNAL ;
    SHAPE ABUTMENT ;
    PORT
      LAYER metal2 ;
      RECT 44.995 0.000 45.065 0.210 ;
    END
  END w0_wd_in[173]
  PIN w0_wd_in[174]
    DIRECTION OUTPUT ;
    USE SIGNAL ;
    SHAPE ABUTMENT ;
    PORT
      LAYER metal2 ;
      RECT 45.565 0.000 45.635 0.210 ;
    END
  END w0_wd_in[174]
  PIN w0_wd_in[175]
    DIRECTION OUTPUT ;
    USE SIGNAL ;
    SHAPE ABUTMENT ;
    PORT
      LAYER metal2 ;
      RECT 46.135 0.000 46.205 0.210 ;
    END
  END w0_wd_in[175]
  PIN w0_wd_in[176]
    DIRECTION OUTPUT ;
    USE SIGNAL ;
    SHAPE ABUTMENT ;
    PORT
      LAYER metal2 ;
      RECT 46.705 0.000 46.775 0.210 ;
    END
  END w0_wd_in[176]
  PIN w0_wd_in[177]
    DIRECTION OUTPUT ;
    USE SIGNAL ;
    SHAPE ABUTMENT ;
    PORT
      LAYER metal2 ;
      RECT 47.275 0.000 47.345 0.210 ;
    END
  END w0_wd_in[177]
  PIN w0_wd_in[178]
    DIRECTION OUTPUT ;
    USE SIGNAL ;
    SHAPE ABUTMENT ;
    PORT
      LAYER metal2 ;
      RECT 47.845 0.000 47.915 0.210 ;
    END
  END w0_wd_in[178]
  PIN w0_wd_in[179]
    DIRECTION OUTPUT ;
    USE SIGNAL ;
    SHAPE ABUTMENT ;
    PORT
      LAYER metal2 ;
      RECT 48.415 0.000 48.485 0.210 ;
    END
  END w0_wd_in[179]
  PIN w0_wd_in[180]
    DIRECTION OUTPUT ;
    USE SIGNAL ;
    SHAPE ABUTMENT ;
    PORT
      LAYER metal2 ;
      RECT 48.985 0.000 49.055 0.210 ;
    END
  END w0_wd_in[180]
  PIN w0_wd_in[181]
    DIRECTION OUTPUT ;
    USE SIGNAL ;
    SHAPE ABUTMENT ;
    PORT
      LAYER metal2 ;
      RECT 49.555 0.000 49.625 0.210 ;
    END
  END w0_wd_in[181]
  PIN w0_wd_in[182]
    DIRECTION OUTPUT ;
    USE SIGNAL ;
    SHAPE ABUTMENT ;
    PORT
      LAYER metal2 ;
      RECT 50.125 0.000 50.195 0.210 ;
    END
  END w0_wd_in[182]
  PIN w0_wd_in[183]
    DIRECTION OUTPUT ;
    USE SIGNAL ;
    SHAPE ABUTMENT ;
    PORT
      LAYER metal2 ;
      RECT 50.695 0.000 50.765 0.210 ;
    END
  END w0_wd_in[183]
  PIN w0_wd_in[184]
    DIRECTION OUTPUT ;
    USE SIGNAL ;
    SHAPE ABUTMENT ;
    PORT
      LAYER metal2 ;
      RECT 51.265 0.000 51.335 0.210 ;
    END
  END w0_wd_in[184]
  PIN w0_wd_in[185]
    DIRECTION OUTPUT ;
    USE SIGNAL ;
    SHAPE ABUTMENT ;
    PORT
      LAYER metal2 ;
      RECT 51.835 0.000 51.905 0.210 ;
    END
  END w0_wd_in[185]
  PIN w0_wd_in[186]
    DIRECTION OUTPUT ;
    USE SIGNAL ;
    SHAPE ABUTMENT ;
    PORT
      LAYER metal2 ;
      RECT 52.405 0.000 52.475 0.210 ;
    END
  END w0_wd_in[186]
  PIN w0_wd_in[187]
    DIRECTION OUTPUT ;
    USE SIGNAL ;
    SHAPE ABUTMENT ;
    PORT
      LAYER metal2 ;
      RECT 52.975 0.000 53.045 0.210 ;
    END
  END w0_wd_in[187]
  PIN w0_wd_in[188]
    DIRECTION OUTPUT ;
    USE SIGNAL ;
    SHAPE ABUTMENT ;
    PORT
      LAYER metal2 ;
      RECT 53.545 0.000 53.615 0.210 ;
    END
  END w0_wd_in[188]
  PIN w0_wd_in[189]
    DIRECTION OUTPUT ;
    USE SIGNAL ;
    SHAPE ABUTMENT ;
    PORT
      LAYER metal2 ;
      RECT 54.115 0.000 54.185 0.210 ;
    END
  END w0_wd_in[189]
  PIN w0_wd_in[190]
    DIRECTION OUTPUT ;
    USE SIGNAL ;
    SHAPE ABUTMENT ;
    PORT
      LAYER metal2 ;
      RECT 54.685 0.000 54.755 0.210 ;
    END
  END w0_wd_in[190]
  PIN w0_wd_in[191]
    DIRECTION OUTPUT ;
    USE SIGNAL ;
    SHAPE ABUTMENT ;
    PORT
      LAYER metal2 ;
      RECT 55.255 0.000 55.325 0.210 ;
    END
  END w0_wd_in[191]
  PIN r0_rd_out[0]
    DIRECTION OUTPUT ;
    USE SIGNAL ;
    SHAPE ABUTMENT ;
    PORT
      LAYER metal2 ;
      RECT 55.825 0.000 55.895 0.210 ;
    END
  END r0_rd_out[0]
  PIN r0_rd_out[1]
    DIRECTION OUTPUT ;
    USE SIGNAL ;
    SHAPE ABUTMENT ;
    PORT
      LAYER metal2 ;
      RECT 56.395 0.000 56.465 0.210 ;
    END
  END r0_rd_out[1]
  PIN r0_rd_out[2]
    DIRECTION OUTPUT ;
    USE SIGNAL ;
    SHAPE ABUTMENT ;
    PORT
      LAYER metal2 ;
      RECT 56.965 0.000 57.035 0.210 ;
    END
  END r0_rd_out[2]
  PIN r0_rd_out[3]
    DIRECTION OUTPUT ;
    USE SIGNAL ;
    SHAPE ABUTMENT ;
    PORT
      LAYER metal2 ;
      RECT 57.535 0.000 57.605 0.210 ;
    END
  END r0_rd_out[3]
  PIN r0_rd_out[4]
    DIRECTION OUTPUT ;
    USE SIGNAL ;
    SHAPE ABUTMENT ;
    PORT
      LAYER metal2 ;
      RECT 58.105 0.000 58.175 0.210 ;
    END
  END r0_rd_out[4]
  PIN r0_rd_out[5]
    DIRECTION OUTPUT ;
    USE SIGNAL ;
    SHAPE ABUTMENT ;
    PORT
      LAYER metal2 ;
      RECT 58.675 0.000 58.745 0.210 ;
    END
  END r0_rd_out[5]
  PIN r0_rd_out[6]
    DIRECTION OUTPUT ;
    USE SIGNAL ;
    SHAPE ABUTMENT ;
    PORT
      LAYER metal2 ;
      RECT 59.245 0.000 59.315 0.210 ;
    END
  END r0_rd_out[6]
  PIN r0_rd_out[7]
    DIRECTION OUTPUT ;
    USE SIGNAL ;
    SHAPE ABUTMENT ;
    PORT
      LAYER metal2 ;
      RECT 59.815 0.000 59.885 0.210 ;
    END
  END r0_rd_out[7]
  PIN r0_rd_out[8]
    DIRECTION OUTPUT ;
    USE SIGNAL ;
    SHAPE ABUTMENT ;
    PORT
      LAYER metal2 ;
      RECT 60.385 0.000 60.455 0.210 ;
    END
  END r0_rd_out[8]
  PIN r0_rd_out[9]
    DIRECTION OUTPUT ;
    USE SIGNAL ;
    SHAPE ABUTMENT ;
    PORT
      LAYER metal2 ;
      RECT 60.955 0.000 61.025 0.210 ;
    END
  END r0_rd_out[9]
  PIN r0_rd_out[10]
    DIRECTION OUTPUT ;
    USE SIGNAL ;
    SHAPE ABUTMENT ;
    PORT
      LAYER metal2 ;
      RECT 61.525 0.000 61.595 0.210 ;
    END
  END r0_rd_out[10]
  PIN r0_rd_out[11]
    DIRECTION OUTPUT ;
    USE SIGNAL ;
    SHAPE ABUTMENT ;
    PORT
      LAYER metal2 ;
      RECT 62.095 0.000 62.165 0.210 ;
    END
  END r0_rd_out[11]
  PIN r0_rd_out[12]
    DIRECTION OUTPUT ;
    USE SIGNAL ;
    SHAPE ABUTMENT ;
    PORT
      LAYER metal2 ;
      RECT 62.665 0.000 62.735 0.210 ;
    END
  END r0_rd_out[12]
  PIN r0_rd_out[13]
    DIRECTION OUTPUT ;
    USE SIGNAL ;
    SHAPE ABUTMENT ;
    PORT
      LAYER metal2 ;
      RECT 63.235 0.000 63.305 0.210 ;
    END
  END r0_rd_out[13]
  PIN r0_rd_out[14]
    DIRECTION OUTPUT ;
    USE SIGNAL ;
    SHAPE ABUTMENT ;
    PORT
      LAYER metal2 ;
      RECT 63.805 0.000 63.875 0.210 ;
    END
  END r0_rd_out[14]
  PIN r0_rd_out[15]
    DIRECTION OUTPUT ;
    USE SIGNAL ;
    SHAPE ABUTMENT ;
    PORT
      LAYER metal2 ;
      RECT 64.375 0.000 64.445 0.210 ;
    END
  END r0_rd_out[15]
  PIN r0_rd_out[16]
    DIRECTION OUTPUT ;
    USE SIGNAL ;
    SHAPE ABUTMENT ;
    PORT
      LAYER metal2 ;
      RECT 64.945 0.000 65.015 0.210 ;
    END
  END r0_rd_out[16]
  PIN r0_rd_out[17]
    DIRECTION OUTPUT ;
    USE SIGNAL ;
    SHAPE ABUTMENT ;
    PORT
      LAYER metal2 ;
      RECT 65.515 0.000 65.585 0.210 ;
    END
  END r0_rd_out[17]
  PIN r0_rd_out[18]
    DIRECTION OUTPUT ;
    USE SIGNAL ;
    SHAPE ABUTMENT ;
    PORT
      LAYER metal2 ;
      RECT 66.085 0.000 66.155 0.210 ;
    END
  END r0_rd_out[18]
  PIN r0_rd_out[19]
    DIRECTION OUTPUT ;
    USE SIGNAL ;
    SHAPE ABUTMENT ;
    PORT
      LAYER metal2 ;
      RECT 66.655 0.000 66.725 0.210 ;
    END
  END r0_rd_out[19]
  PIN r0_rd_out[20]
    DIRECTION OUTPUT ;
    USE SIGNAL ;
    SHAPE ABUTMENT ;
    PORT
      LAYER metal2 ;
      RECT 67.225 0.000 67.295 0.210 ;
    END
  END r0_rd_out[20]
  PIN r0_rd_out[21]
    DIRECTION OUTPUT ;
    USE SIGNAL ;
    SHAPE ABUTMENT ;
    PORT
      LAYER metal2 ;
      RECT 67.795 0.000 67.865 0.210 ;
    END
  END r0_rd_out[21]
  PIN r0_rd_out[22]
    DIRECTION OUTPUT ;
    USE SIGNAL ;
    SHAPE ABUTMENT ;
    PORT
      LAYER metal2 ;
      RECT 68.365 0.000 68.435 0.210 ;
    END
  END r0_rd_out[22]
  PIN r0_rd_out[23]
    DIRECTION OUTPUT ;
    USE SIGNAL ;
    SHAPE ABUTMENT ;
    PORT
      LAYER metal2 ;
      RECT 68.935 0.000 69.005 0.210 ;
    END
  END r0_rd_out[23]
  PIN r0_rd_out[24]
    DIRECTION OUTPUT ;
    USE SIGNAL ;
    SHAPE ABUTMENT ;
    PORT
      LAYER metal2 ;
      RECT 69.505 0.000 69.575 0.210 ;
    END
  END r0_rd_out[24]
  PIN r0_rd_out[25]
    DIRECTION OUTPUT ;
    USE SIGNAL ;
    SHAPE ABUTMENT ;
    PORT
      LAYER metal2 ;
      RECT 70.075 0.000 70.145 0.210 ;
    END
  END r0_rd_out[25]
  PIN r0_rd_out[26]
    DIRECTION OUTPUT ;
    USE SIGNAL ;
    SHAPE ABUTMENT ;
    PORT
      LAYER metal2 ;
      RECT 70.645 0.000 70.715 0.210 ;
    END
  END r0_rd_out[26]
  PIN r0_rd_out[27]
    DIRECTION OUTPUT ;
    USE SIGNAL ;
    SHAPE ABUTMENT ;
    PORT
      LAYER metal2 ;
      RECT 71.215 0.000 71.285 0.210 ;
    END
  END r0_rd_out[27]
  PIN r0_rd_out[28]
    DIRECTION OUTPUT ;
    USE SIGNAL ;
    SHAPE ABUTMENT ;
    PORT
      LAYER metal2 ;
      RECT 71.785 0.000 71.855 0.210 ;
    END
  END r0_rd_out[28]
  PIN r0_rd_out[29]
    DIRECTION OUTPUT ;
    USE SIGNAL ;
    SHAPE ABUTMENT ;
    PORT
      LAYER metal2 ;
      RECT 72.355 0.000 72.425 0.210 ;
    END
  END r0_rd_out[29]
  PIN r0_rd_out[30]
    DIRECTION OUTPUT ;
    USE SIGNAL ;
    SHAPE ABUTMENT ;
    PORT
      LAYER metal2 ;
      RECT 72.925 0.000 72.995 0.210 ;
    END
  END r0_rd_out[30]
  PIN r0_rd_out[31]
    DIRECTION OUTPUT ;
    USE SIGNAL ;
    SHAPE ABUTMENT ;
    PORT
      LAYER metal2 ;
      RECT 73.495 0.000 73.565 0.210 ;
    END
  END r0_rd_out[31]
  PIN r0_rd_out[32]
    DIRECTION OUTPUT ;
    USE SIGNAL ;
    SHAPE ABUTMENT ;
    PORT
      LAYER metal2 ;
      RECT 74.065 0.000 74.135 0.210 ;
    END
  END r0_rd_out[32]
  PIN r0_rd_out[33]
    DIRECTION OUTPUT ;
    USE SIGNAL ;
    SHAPE ABUTMENT ;
    PORT
      LAYER metal2 ;
      RECT 74.635 0.000 74.705 0.210 ;
    END
  END r0_rd_out[33]
  PIN r0_rd_out[34]
    DIRECTION OUTPUT ;
    USE SIGNAL ;
    SHAPE ABUTMENT ;
    PORT
      LAYER metal2 ;
      RECT 75.205 0.000 75.275 0.210 ;
    END
  END r0_rd_out[34]
  PIN r0_rd_out[35]
    DIRECTION OUTPUT ;
    USE SIGNAL ;
    SHAPE ABUTMENT ;
    PORT
      LAYER metal2 ;
      RECT 75.775 0.000 75.845 0.210 ;
    END
  END r0_rd_out[35]
  PIN r0_rd_out[36]
    DIRECTION OUTPUT ;
    USE SIGNAL ;
    SHAPE ABUTMENT ;
    PORT
      LAYER metal2 ;
      RECT 76.345 0.000 76.415 0.210 ;
    END
  END r0_rd_out[36]
  PIN r0_rd_out[37]
    DIRECTION OUTPUT ;
    USE SIGNAL ;
    SHAPE ABUTMENT ;
    PORT
      LAYER metal2 ;
      RECT 76.915 0.000 76.985 0.210 ;
    END
  END r0_rd_out[37]
  PIN r0_rd_out[38]
    DIRECTION OUTPUT ;
    USE SIGNAL ;
    SHAPE ABUTMENT ;
    PORT
      LAYER metal2 ;
      RECT 77.485 0.000 77.555 0.210 ;
    END
  END r0_rd_out[38]
  PIN r0_rd_out[39]
    DIRECTION OUTPUT ;
    USE SIGNAL ;
    SHAPE ABUTMENT ;
    PORT
      LAYER metal2 ;
      RECT 78.055 0.000 78.125 0.210 ;
    END
  END r0_rd_out[39]
  PIN r0_rd_out[40]
    DIRECTION OUTPUT ;
    USE SIGNAL ;
    SHAPE ABUTMENT ;
    PORT
      LAYER metal2 ;
      RECT 78.625 0.000 78.695 0.210 ;
    END
  END r0_rd_out[40]
  PIN r0_rd_out[41]
    DIRECTION OUTPUT ;
    USE SIGNAL ;
    SHAPE ABUTMENT ;
    PORT
      LAYER metal2 ;
      RECT 79.195 0.000 79.265 0.210 ;
    END
  END r0_rd_out[41]
  PIN r0_rd_out[42]
    DIRECTION OUTPUT ;
    USE SIGNAL ;
    SHAPE ABUTMENT ;
    PORT
      LAYER metal2 ;
      RECT 79.765 0.000 79.835 0.210 ;
    END
  END r0_rd_out[42]
  PIN r0_rd_out[43]
    DIRECTION OUTPUT ;
    USE SIGNAL ;
    SHAPE ABUTMENT ;
    PORT
      LAYER metal2 ;
      RECT 80.335 0.000 80.405 0.210 ;
    END
  END r0_rd_out[43]
  PIN r0_rd_out[44]
    DIRECTION OUTPUT ;
    USE SIGNAL ;
    SHAPE ABUTMENT ;
    PORT
      LAYER metal2 ;
      RECT 80.905 0.000 80.975 0.210 ;
    END
  END r0_rd_out[44]
  PIN r0_rd_out[45]
    DIRECTION OUTPUT ;
    USE SIGNAL ;
    SHAPE ABUTMENT ;
    PORT
      LAYER metal2 ;
      RECT 81.475 0.000 81.545 0.210 ;
    END
  END r0_rd_out[45]
  PIN r0_rd_out[46]
    DIRECTION OUTPUT ;
    USE SIGNAL ;
    SHAPE ABUTMENT ;
    PORT
      LAYER metal2 ;
      RECT 82.045 0.000 82.115 0.210 ;
    END
  END r0_rd_out[46]
  PIN r0_rd_out[47]
    DIRECTION OUTPUT ;
    USE SIGNAL ;
    SHAPE ABUTMENT ;
    PORT
      LAYER metal2 ;
      RECT 82.615 0.000 82.685 0.210 ;
    END
  END r0_rd_out[47]
  PIN r0_rd_out[48]
    DIRECTION OUTPUT ;
    USE SIGNAL ;
    SHAPE ABUTMENT ;
    PORT
      LAYER metal2 ;
      RECT 83.185 0.000 83.255 0.210 ;
    END
  END r0_rd_out[48]
  PIN r0_rd_out[49]
    DIRECTION OUTPUT ;
    USE SIGNAL ;
    SHAPE ABUTMENT ;
    PORT
      LAYER metal2 ;
      RECT 83.755 0.000 83.825 0.210 ;
    END
  END r0_rd_out[49]
  PIN r0_rd_out[50]
    DIRECTION OUTPUT ;
    USE SIGNAL ;
    SHAPE ABUTMENT ;
    PORT
      LAYER metal2 ;
      RECT 84.325 0.000 84.395 0.210 ;
    END
  END r0_rd_out[50]
  PIN r0_rd_out[51]
    DIRECTION OUTPUT ;
    USE SIGNAL ;
    SHAPE ABUTMENT ;
    PORT
      LAYER metal2 ;
      RECT 84.895 0.000 84.965 0.210 ;
    END
  END r0_rd_out[51]
  PIN r0_rd_out[52]
    DIRECTION OUTPUT ;
    USE SIGNAL ;
    SHAPE ABUTMENT ;
    PORT
      LAYER metal2 ;
      RECT 85.465 0.000 85.535 0.210 ;
    END
  END r0_rd_out[52]
  PIN r0_rd_out[53]
    DIRECTION OUTPUT ;
    USE SIGNAL ;
    SHAPE ABUTMENT ;
    PORT
      LAYER metal2 ;
      RECT 86.035 0.000 86.105 0.210 ;
    END
  END r0_rd_out[53]
  PIN r0_rd_out[54]
    DIRECTION OUTPUT ;
    USE SIGNAL ;
    SHAPE ABUTMENT ;
    PORT
      LAYER metal2 ;
      RECT 86.605 0.000 86.675 0.210 ;
    END
  END r0_rd_out[54]
  PIN r0_rd_out[55]
    DIRECTION OUTPUT ;
    USE SIGNAL ;
    SHAPE ABUTMENT ;
    PORT
      LAYER metal2 ;
      RECT 87.175 0.000 87.245 0.210 ;
    END
  END r0_rd_out[55]
  PIN r0_rd_out[56]
    DIRECTION OUTPUT ;
    USE SIGNAL ;
    SHAPE ABUTMENT ;
    PORT
      LAYER metal2 ;
      RECT 87.745 0.000 87.815 0.210 ;
    END
  END r0_rd_out[56]
  PIN r0_rd_out[57]
    DIRECTION OUTPUT ;
    USE SIGNAL ;
    SHAPE ABUTMENT ;
    PORT
      LAYER metal2 ;
      RECT 88.315 0.000 88.385 0.210 ;
    END
  END r0_rd_out[57]
  PIN r0_rd_out[58]
    DIRECTION OUTPUT ;
    USE SIGNAL ;
    SHAPE ABUTMENT ;
    PORT
      LAYER metal2 ;
      RECT 88.885 0.000 88.955 0.210 ;
    END
  END r0_rd_out[58]
  PIN r0_rd_out[59]
    DIRECTION OUTPUT ;
    USE SIGNAL ;
    SHAPE ABUTMENT ;
    PORT
      LAYER metal2 ;
      RECT 89.455 0.000 89.525 0.210 ;
    END
  END r0_rd_out[59]
  PIN r0_rd_out[60]
    DIRECTION OUTPUT ;
    USE SIGNAL ;
    SHAPE ABUTMENT ;
    PORT
      LAYER metal2 ;
      RECT 90.025 0.000 90.095 0.210 ;
    END
  END r0_rd_out[60]
  PIN r0_rd_out[61]
    DIRECTION OUTPUT ;
    USE SIGNAL ;
    SHAPE ABUTMENT ;
    PORT
      LAYER metal2 ;
      RECT 90.595 0.000 90.665 0.210 ;
    END
  END r0_rd_out[61]
  PIN r0_rd_out[62]
    DIRECTION OUTPUT ;
    USE SIGNAL ;
    SHAPE ABUTMENT ;
    PORT
      LAYER metal2 ;
      RECT 91.165 0.000 91.235 0.210 ;
    END
  END r0_rd_out[62]
  PIN r0_rd_out[63]
    DIRECTION OUTPUT ;
    USE SIGNAL ;
    SHAPE ABUTMENT ;
    PORT
      LAYER metal2 ;
      RECT 91.735 0.000 91.805 0.210 ;
    END
  END r0_rd_out[63]
  PIN r0_rd_out[64]
    DIRECTION OUTPUT ;
    USE SIGNAL ;
    SHAPE ABUTMENT ;
    PORT
      LAYER metal2 ;
      RECT 92.305 0.000 92.375 0.210 ;
    END
  END r0_rd_out[64]
  PIN r0_rd_out[65]
    DIRECTION OUTPUT ;
    USE SIGNAL ;
    SHAPE ABUTMENT ;
    PORT
      LAYER metal2 ;
      RECT 92.875 0.000 92.945 0.210 ;
    END
  END r0_rd_out[65]
  PIN r0_rd_out[66]
    DIRECTION OUTPUT ;
    USE SIGNAL ;
    SHAPE ABUTMENT ;
    PORT
      LAYER metal2 ;
      RECT 93.445 0.000 93.515 0.210 ;
    END
  END r0_rd_out[66]
  PIN r0_rd_out[67]
    DIRECTION OUTPUT ;
    USE SIGNAL ;
    SHAPE ABUTMENT ;
    PORT
      LAYER metal2 ;
      RECT 94.015 0.000 94.085 0.210 ;
    END
  END r0_rd_out[67]
  PIN r0_rd_out[68]
    DIRECTION OUTPUT ;
    USE SIGNAL ;
    SHAPE ABUTMENT ;
    PORT
      LAYER metal2 ;
      RECT 94.585 0.000 94.655 0.210 ;
    END
  END r0_rd_out[68]
  PIN r0_rd_out[69]
    DIRECTION OUTPUT ;
    USE SIGNAL ;
    SHAPE ABUTMENT ;
    PORT
      LAYER metal2 ;
      RECT 95.155 0.000 95.225 0.210 ;
    END
  END r0_rd_out[69]
  PIN r0_rd_out[70]
    DIRECTION OUTPUT ;
    USE SIGNAL ;
    SHAPE ABUTMENT ;
    PORT
      LAYER metal2 ;
      RECT 95.725 0.000 95.795 0.210 ;
    END
  END r0_rd_out[70]
  PIN r0_rd_out[71]
    DIRECTION OUTPUT ;
    USE SIGNAL ;
    SHAPE ABUTMENT ;
    PORT
      LAYER metal2 ;
      RECT 96.295 0.000 96.365 0.210 ;
    END
  END r0_rd_out[71]
  PIN r0_rd_out[72]
    DIRECTION OUTPUT ;
    USE SIGNAL ;
    SHAPE ABUTMENT ;
    PORT
      LAYER metal2 ;
      RECT 96.865 0.000 96.935 0.210 ;
    END
  END r0_rd_out[72]
  PIN r0_rd_out[73]
    DIRECTION OUTPUT ;
    USE SIGNAL ;
    SHAPE ABUTMENT ;
    PORT
      LAYER metal2 ;
      RECT 97.435 0.000 97.505 0.210 ;
    END
  END r0_rd_out[73]
  PIN r0_rd_out[74]
    DIRECTION OUTPUT ;
    USE SIGNAL ;
    SHAPE ABUTMENT ;
    PORT
      LAYER metal2 ;
      RECT 98.005 0.000 98.075 0.210 ;
    END
  END r0_rd_out[74]
  PIN r0_rd_out[75]
    DIRECTION OUTPUT ;
    USE SIGNAL ;
    SHAPE ABUTMENT ;
    PORT
      LAYER metal2 ;
      RECT 98.575 0.000 98.645 0.210 ;
    END
  END r0_rd_out[75]
  PIN r0_rd_out[76]
    DIRECTION OUTPUT ;
    USE SIGNAL ;
    SHAPE ABUTMENT ;
    PORT
      LAYER metal2 ;
      RECT 99.145 0.000 99.215 0.210 ;
    END
  END r0_rd_out[76]
  PIN r0_rd_out[77]
    DIRECTION OUTPUT ;
    USE SIGNAL ;
    SHAPE ABUTMENT ;
    PORT
      LAYER metal2 ;
      RECT 99.715 0.000 99.785 0.210 ;
    END
  END r0_rd_out[77]
  PIN r0_rd_out[78]
    DIRECTION OUTPUT ;
    USE SIGNAL ;
    SHAPE ABUTMENT ;
    PORT
      LAYER metal2 ;
      RECT 100.285 0.000 100.355 0.210 ;
    END
  END r0_rd_out[78]
  PIN r0_rd_out[79]
    DIRECTION OUTPUT ;
    USE SIGNAL ;
    SHAPE ABUTMENT ;
    PORT
      LAYER metal2 ;
      RECT 100.855 0.000 100.925 0.210 ;
    END
  END r0_rd_out[79]
  PIN r0_rd_out[80]
    DIRECTION OUTPUT ;
    USE SIGNAL ;
    SHAPE ABUTMENT ;
    PORT
      LAYER metal2 ;
      RECT 101.425 0.000 101.495 0.210 ;
    END
  END r0_rd_out[80]
  PIN r0_rd_out[81]
    DIRECTION OUTPUT ;
    USE SIGNAL ;
    SHAPE ABUTMENT ;
    PORT
      LAYER metal2 ;
      RECT 101.995 0.000 102.065 0.210 ;
    END
  END r0_rd_out[81]
  PIN r0_rd_out[82]
    DIRECTION OUTPUT ;
    USE SIGNAL ;
    SHAPE ABUTMENT ;
    PORT
      LAYER metal2 ;
      RECT 102.565 0.000 102.635 0.210 ;
    END
  END r0_rd_out[82]
  PIN r0_rd_out[83]
    DIRECTION OUTPUT ;
    USE SIGNAL ;
    SHAPE ABUTMENT ;
    PORT
      LAYER metal2 ;
      RECT 103.135 0.000 103.205 0.210 ;
    END
  END r0_rd_out[83]
  PIN r0_rd_out[84]
    DIRECTION OUTPUT ;
    USE SIGNAL ;
    SHAPE ABUTMENT ;
    PORT
      LAYER metal2 ;
      RECT 103.705 0.000 103.775 0.210 ;
    END
  END r0_rd_out[84]
  PIN r0_rd_out[85]
    DIRECTION OUTPUT ;
    USE SIGNAL ;
    SHAPE ABUTMENT ;
    PORT
      LAYER metal2 ;
      RECT 104.275 0.000 104.345 0.210 ;
    END
  END r0_rd_out[85]
  PIN r0_rd_out[86]
    DIRECTION OUTPUT ;
    USE SIGNAL ;
    SHAPE ABUTMENT ;
    PORT
      LAYER metal2 ;
      RECT 104.845 0.000 104.915 0.210 ;
    END
  END r0_rd_out[86]
  PIN r0_rd_out[87]
    DIRECTION OUTPUT ;
    USE SIGNAL ;
    SHAPE ABUTMENT ;
    PORT
      LAYER metal2 ;
      RECT 105.415 0.000 105.485 0.210 ;
    END
  END r0_rd_out[87]
  PIN r0_rd_out[88]
    DIRECTION OUTPUT ;
    USE SIGNAL ;
    SHAPE ABUTMENT ;
    PORT
      LAYER metal2 ;
      RECT 105.985 0.000 106.055 0.210 ;
    END
  END r0_rd_out[88]
  PIN r0_rd_out[89]
    DIRECTION OUTPUT ;
    USE SIGNAL ;
    SHAPE ABUTMENT ;
    PORT
      LAYER metal2 ;
      RECT 106.555 0.000 106.625 0.210 ;
    END
  END r0_rd_out[89]
  PIN r0_rd_out[90]
    DIRECTION OUTPUT ;
    USE SIGNAL ;
    SHAPE ABUTMENT ;
    PORT
      LAYER metal2 ;
      RECT 107.125 0.000 107.195 0.210 ;
    END
  END r0_rd_out[90]
  PIN r0_rd_out[91]
    DIRECTION OUTPUT ;
    USE SIGNAL ;
    SHAPE ABUTMENT ;
    PORT
      LAYER metal2 ;
      RECT 107.695 0.000 107.765 0.210 ;
    END
  END r0_rd_out[91]
  PIN r0_rd_out[92]
    DIRECTION OUTPUT ;
    USE SIGNAL ;
    SHAPE ABUTMENT ;
    PORT
      LAYER metal2 ;
      RECT 108.265 0.000 108.335 0.210 ;
    END
  END r0_rd_out[92]
  PIN r0_rd_out[93]
    DIRECTION OUTPUT ;
    USE SIGNAL ;
    SHAPE ABUTMENT ;
    PORT
      LAYER metal2 ;
      RECT 108.835 0.000 108.905 0.210 ;
    END
  END r0_rd_out[93]
  PIN r0_rd_out[94]
    DIRECTION OUTPUT ;
    USE SIGNAL ;
    SHAPE ABUTMENT ;
    PORT
      LAYER metal2 ;
      RECT 109.405 0.000 109.475 0.210 ;
    END
  END r0_rd_out[94]
  PIN r0_rd_out[95]
    DIRECTION OUTPUT ;
    USE SIGNAL ;
    SHAPE ABUTMENT ;
    PORT
      LAYER metal2 ;
      RECT 109.975 0.000 110.045 0.210 ;
    END
  END r0_rd_out[95]
  PIN r0_rd_out[96]
    DIRECTION OUTPUT ;
    USE SIGNAL ;
    SHAPE ABUTMENT ;
    PORT
      LAYER metal2 ;
      RECT 55.825 208.390 55.895 208.600 ;
    END
  END r0_rd_out[96]
  PIN r0_rd_out[97]
    DIRECTION OUTPUT ;
    USE SIGNAL ;
    SHAPE ABUTMENT ;
    PORT
      LAYER metal2 ;
      RECT 56.395 208.390 56.465 208.600 ;
    END
  END r0_rd_out[97]
  PIN r0_rd_out[98]
    DIRECTION OUTPUT ;
    USE SIGNAL ;
    SHAPE ABUTMENT ;
    PORT
      LAYER metal2 ;
      RECT 56.965 208.390 57.035 208.600 ;
    END
  END r0_rd_out[98]
  PIN r0_rd_out[99]
    DIRECTION OUTPUT ;
    USE SIGNAL ;
    SHAPE ABUTMENT ;
    PORT
      LAYER metal2 ;
      RECT 57.535 208.390 57.605 208.600 ;
    END
  END r0_rd_out[99]
  PIN r0_rd_out[100]
    DIRECTION OUTPUT ;
    USE SIGNAL ;
    SHAPE ABUTMENT ;
    PORT
      LAYER metal2 ;
      RECT 58.105 208.390 58.175 208.600 ;
    END
  END r0_rd_out[100]
  PIN r0_rd_out[101]
    DIRECTION OUTPUT ;
    USE SIGNAL ;
    SHAPE ABUTMENT ;
    PORT
      LAYER metal2 ;
      RECT 58.675 208.390 58.745 208.600 ;
    END
  END r0_rd_out[101]
  PIN r0_rd_out[102]
    DIRECTION OUTPUT ;
    USE SIGNAL ;
    SHAPE ABUTMENT ;
    PORT
      LAYER metal2 ;
      RECT 59.245 208.390 59.315 208.600 ;
    END
  END r0_rd_out[102]
  PIN r0_rd_out[103]
    DIRECTION OUTPUT ;
    USE SIGNAL ;
    SHAPE ABUTMENT ;
    PORT
      LAYER metal2 ;
      RECT 59.815 208.390 59.885 208.600 ;
    END
  END r0_rd_out[103]
  PIN r0_rd_out[104]
    DIRECTION OUTPUT ;
    USE SIGNAL ;
    SHAPE ABUTMENT ;
    PORT
      LAYER metal2 ;
      RECT 60.385 208.390 60.455 208.600 ;
    END
  END r0_rd_out[104]
  PIN r0_rd_out[105]
    DIRECTION OUTPUT ;
    USE SIGNAL ;
    SHAPE ABUTMENT ;
    PORT
      LAYER metal2 ;
      RECT 60.955 208.390 61.025 208.600 ;
    END
  END r0_rd_out[105]
  PIN r0_rd_out[106]
    DIRECTION OUTPUT ;
    USE SIGNAL ;
    SHAPE ABUTMENT ;
    PORT
      LAYER metal2 ;
      RECT 61.525 208.390 61.595 208.600 ;
    END
  END r0_rd_out[106]
  PIN r0_rd_out[107]
    DIRECTION OUTPUT ;
    USE SIGNAL ;
    SHAPE ABUTMENT ;
    PORT
      LAYER metal2 ;
      RECT 62.095 208.390 62.165 208.600 ;
    END
  END r0_rd_out[107]
  PIN r0_rd_out[108]
    DIRECTION OUTPUT ;
    USE SIGNAL ;
    SHAPE ABUTMENT ;
    PORT
      LAYER metal2 ;
      RECT 62.665 208.390 62.735 208.600 ;
    END
  END r0_rd_out[108]
  PIN r0_rd_out[109]
    DIRECTION OUTPUT ;
    USE SIGNAL ;
    SHAPE ABUTMENT ;
    PORT
      LAYER metal2 ;
      RECT 63.235 208.390 63.305 208.600 ;
    END
  END r0_rd_out[109]
  PIN r0_rd_out[110]
    DIRECTION OUTPUT ;
    USE SIGNAL ;
    SHAPE ABUTMENT ;
    PORT
      LAYER metal2 ;
      RECT 63.805 208.390 63.875 208.600 ;
    END
  END r0_rd_out[110]
  PIN r0_rd_out[111]
    DIRECTION OUTPUT ;
    USE SIGNAL ;
    SHAPE ABUTMENT ;
    PORT
      LAYER metal2 ;
      RECT 64.375 208.390 64.445 208.600 ;
    END
  END r0_rd_out[111]
  PIN r0_rd_out[112]
    DIRECTION OUTPUT ;
    USE SIGNAL ;
    SHAPE ABUTMENT ;
    PORT
      LAYER metal2 ;
      RECT 64.945 208.390 65.015 208.600 ;
    END
  END r0_rd_out[112]
  PIN r0_rd_out[113]
    DIRECTION OUTPUT ;
    USE SIGNAL ;
    SHAPE ABUTMENT ;
    PORT
      LAYER metal2 ;
      RECT 65.515 208.390 65.585 208.600 ;
    END
  END r0_rd_out[113]
  PIN r0_rd_out[114]
    DIRECTION OUTPUT ;
    USE SIGNAL ;
    SHAPE ABUTMENT ;
    PORT
      LAYER metal2 ;
      RECT 66.085 208.390 66.155 208.600 ;
    END
  END r0_rd_out[114]
  PIN r0_rd_out[115]
    DIRECTION OUTPUT ;
    USE SIGNAL ;
    SHAPE ABUTMENT ;
    PORT
      LAYER metal2 ;
      RECT 66.655 208.390 66.725 208.600 ;
    END
  END r0_rd_out[115]
  PIN r0_rd_out[116]
    DIRECTION OUTPUT ;
    USE SIGNAL ;
    SHAPE ABUTMENT ;
    PORT
      LAYER metal2 ;
      RECT 67.225 208.390 67.295 208.600 ;
    END
  END r0_rd_out[116]
  PIN r0_rd_out[117]
    DIRECTION OUTPUT ;
    USE SIGNAL ;
    SHAPE ABUTMENT ;
    PORT
      LAYER metal2 ;
      RECT 67.795 208.390 67.865 208.600 ;
    END
  END r0_rd_out[117]
  PIN r0_rd_out[118]
    DIRECTION OUTPUT ;
    USE SIGNAL ;
    SHAPE ABUTMENT ;
    PORT
      LAYER metal2 ;
      RECT 68.365 208.390 68.435 208.600 ;
    END
  END r0_rd_out[118]
  PIN r0_rd_out[119]
    DIRECTION OUTPUT ;
    USE SIGNAL ;
    SHAPE ABUTMENT ;
    PORT
      LAYER metal2 ;
      RECT 68.935 208.390 69.005 208.600 ;
    END
  END r0_rd_out[119]
  PIN r0_rd_out[120]
    DIRECTION OUTPUT ;
    USE SIGNAL ;
    SHAPE ABUTMENT ;
    PORT
      LAYER metal2 ;
      RECT 69.505 208.390 69.575 208.600 ;
    END
  END r0_rd_out[120]
  PIN r0_rd_out[121]
    DIRECTION OUTPUT ;
    USE SIGNAL ;
    SHAPE ABUTMENT ;
    PORT
      LAYER metal2 ;
      RECT 70.075 208.390 70.145 208.600 ;
    END
  END r0_rd_out[121]
  PIN r0_rd_out[122]
    DIRECTION OUTPUT ;
    USE SIGNAL ;
    SHAPE ABUTMENT ;
    PORT
      LAYER metal2 ;
      RECT 70.645 208.390 70.715 208.600 ;
    END
  END r0_rd_out[122]
  PIN r0_rd_out[123]
    DIRECTION OUTPUT ;
    USE SIGNAL ;
    SHAPE ABUTMENT ;
    PORT
      LAYER metal2 ;
      RECT 71.215 208.390 71.285 208.600 ;
    END
  END r0_rd_out[123]
  PIN r0_rd_out[124]
    DIRECTION OUTPUT ;
    USE SIGNAL ;
    SHAPE ABUTMENT ;
    PORT
      LAYER metal2 ;
      RECT 71.785 208.390 71.855 208.600 ;
    END
  END r0_rd_out[124]
  PIN r0_rd_out[125]
    DIRECTION OUTPUT ;
    USE SIGNAL ;
    SHAPE ABUTMENT ;
    PORT
      LAYER metal2 ;
      RECT 72.355 208.390 72.425 208.600 ;
    END
  END r0_rd_out[125]
  PIN r0_rd_out[126]
    DIRECTION OUTPUT ;
    USE SIGNAL ;
    SHAPE ABUTMENT ;
    PORT
      LAYER metal2 ;
      RECT 72.925 208.390 72.995 208.600 ;
    END
  END r0_rd_out[126]
  PIN r0_rd_out[127]
    DIRECTION OUTPUT ;
    USE SIGNAL ;
    SHAPE ABUTMENT ;
    PORT
      LAYER metal2 ;
      RECT 73.495 208.390 73.565 208.600 ;
    END
  END r0_rd_out[127]
  PIN r0_rd_out[128]
    DIRECTION OUTPUT ;
    USE SIGNAL ;
    SHAPE ABUTMENT ;
    PORT
      LAYER metal2 ;
      RECT 74.065 208.390 74.135 208.600 ;
    END
  END r0_rd_out[128]
  PIN r0_rd_out[129]
    DIRECTION OUTPUT ;
    USE SIGNAL ;
    SHAPE ABUTMENT ;
    PORT
      LAYER metal2 ;
      RECT 74.635 208.390 74.705 208.600 ;
    END
  END r0_rd_out[129]
  PIN r0_rd_out[130]
    DIRECTION OUTPUT ;
    USE SIGNAL ;
    SHAPE ABUTMENT ;
    PORT
      LAYER metal2 ;
      RECT 75.205 208.390 75.275 208.600 ;
    END
  END r0_rd_out[130]
  PIN r0_rd_out[131]
    DIRECTION OUTPUT ;
    USE SIGNAL ;
    SHAPE ABUTMENT ;
    PORT
      LAYER metal2 ;
      RECT 75.775 208.390 75.845 208.600 ;
    END
  END r0_rd_out[131]
  PIN r0_rd_out[132]
    DIRECTION OUTPUT ;
    USE SIGNAL ;
    SHAPE ABUTMENT ;
    PORT
      LAYER metal2 ;
      RECT 76.345 208.390 76.415 208.600 ;
    END
  END r0_rd_out[132]
  PIN r0_rd_out[133]
    DIRECTION OUTPUT ;
    USE SIGNAL ;
    SHAPE ABUTMENT ;
    PORT
      LAYER metal2 ;
      RECT 76.915 208.390 76.985 208.600 ;
    END
  END r0_rd_out[133]
  PIN r0_rd_out[134]
    DIRECTION OUTPUT ;
    USE SIGNAL ;
    SHAPE ABUTMENT ;
    PORT
      LAYER metal2 ;
      RECT 77.485 208.390 77.555 208.600 ;
    END
  END r0_rd_out[134]
  PIN r0_rd_out[135]
    DIRECTION OUTPUT ;
    USE SIGNAL ;
    SHAPE ABUTMENT ;
    PORT
      LAYER metal2 ;
      RECT 78.055 208.390 78.125 208.600 ;
    END
  END r0_rd_out[135]
  PIN r0_rd_out[136]
    DIRECTION OUTPUT ;
    USE SIGNAL ;
    SHAPE ABUTMENT ;
    PORT
      LAYER metal2 ;
      RECT 78.625 208.390 78.695 208.600 ;
    END
  END r0_rd_out[136]
  PIN r0_rd_out[137]
    DIRECTION OUTPUT ;
    USE SIGNAL ;
    SHAPE ABUTMENT ;
    PORT
      LAYER metal2 ;
      RECT 79.195 208.390 79.265 208.600 ;
    END
  END r0_rd_out[137]
  PIN r0_rd_out[138]
    DIRECTION OUTPUT ;
    USE SIGNAL ;
    SHAPE ABUTMENT ;
    PORT
      LAYER metal2 ;
      RECT 79.765 208.390 79.835 208.600 ;
    END
  END r0_rd_out[138]
  PIN r0_rd_out[139]
    DIRECTION OUTPUT ;
    USE SIGNAL ;
    SHAPE ABUTMENT ;
    PORT
      LAYER metal2 ;
      RECT 80.335 208.390 80.405 208.600 ;
    END
  END r0_rd_out[139]
  PIN r0_rd_out[140]
    DIRECTION OUTPUT ;
    USE SIGNAL ;
    SHAPE ABUTMENT ;
    PORT
      LAYER metal2 ;
      RECT 80.905 208.390 80.975 208.600 ;
    END
  END r0_rd_out[140]
  PIN r0_rd_out[141]
    DIRECTION OUTPUT ;
    USE SIGNAL ;
    SHAPE ABUTMENT ;
    PORT
      LAYER metal2 ;
      RECT 81.475 208.390 81.545 208.600 ;
    END
  END r0_rd_out[141]
  PIN r0_rd_out[142]
    DIRECTION OUTPUT ;
    USE SIGNAL ;
    SHAPE ABUTMENT ;
    PORT
      LAYER metal2 ;
      RECT 82.045 208.390 82.115 208.600 ;
    END
  END r0_rd_out[142]
  PIN r0_rd_out[143]
    DIRECTION OUTPUT ;
    USE SIGNAL ;
    SHAPE ABUTMENT ;
    PORT
      LAYER metal2 ;
      RECT 82.615 208.390 82.685 208.600 ;
    END
  END r0_rd_out[143]
  PIN r0_rd_out[144]
    DIRECTION OUTPUT ;
    USE SIGNAL ;
    SHAPE ABUTMENT ;
    PORT
      LAYER metal2 ;
      RECT 83.185 208.390 83.255 208.600 ;
    END
  END r0_rd_out[144]
  PIN r0_rd_out[145]
    DIRECTION OUTPUT ;
    USE SIGNAL ;
    SHAPE ABUTMENT ;
    PORT
      LAYER metal2 ;
      RECT 83.755 208.390 83.825 208.600 ;
    END
  END r0_rd_out[145]
  PIN r0_rd_out[146]
    DIRECTION OUTPUT ;
    USE SIGNAL ;
    SHAPE ABUTMENT ;
    PORT
      LAYER metal2 ;
      RECT 84.325 208.390 84.395 208.600 ;
    END
  END r0_rd_out[146]
  PIN r0_rd_out[147]
    DIRECTION OUTPUT ;
    USE SIGNAL ;
    SHAPE ABUTMENT ;
    PORT
      LAYER metal2 ;
      RECT 84.895 208.390 84.965 208.600 ;
    END
  END r0_rd_out[147]
  PIN r0_rd_out[148]
    DIRECTION OUTPUT ;
    USE SIGNAL ;
    SHAPE ABUTMENT ;
    PORT
      LAYER metal2 ;
      RECT 85.465 208.390 85.535 208.600 ;
    END
  END r0_rd_out[148]
  PIN r0_rd_out[149]
    DIRECTION OUTPUT ;
    USE SIGNAL ;
    SHAPE ABUTMENT ;
    PORT
      LAYER metal2 ;
      RECT 86.035 208.390 86.105 208.600 ;
    END
  END r0_rd_out[149]
  PIN r0_rd_out[150]
    DIRECTION OUTPUT ;
    USE SIGNAL ;
    SHAPE ABUTMENT ;
    PORT
      LAYER metal2 ;
      RECT 86.605 208.390 86.675 208.600 ;
    END
  END r0_rd_out[150]
  PIN r0_rd_out[151]
    DIRECTION OUTPUT ;
    USE SIGNAL ;
    SHAPE ABUTMENT ;
    PORT
      LAYER metal2 ;
      RECT 87.175 208.390 87.245 208.600 ;
    END
  END r0_rd_out[151]
  PIN r0_rd_out[152]
    DIRECTION OUTPUT ;
    USE SIGNAL ;
    SHAPE ABUTMENT ;
    PORT
      LAYER metal2 ;
      RECT 87.745 208.390 87.815 208.600 ;
    END
  END r0_rd_out[152]
  PIN r0_rd_out[153]
    DIRECTION OUTPUT ;
    USE SIGNAL ;
    SHAPE ABUTMENT ;
    PORT
      LAYER metal2 ;
      RECT 88.315 208.390 88.385 208.600 ;
    END
  END r0_rd_out[153]
  PIN r0_rd_out[154]
    DIRECTION OUTPUT ;
    USE SIGNAL ;
    SHAPE ABUTMENT ;
    PORT
      LAYER metal2 ;
      RECT 88.885 208.390 88.955 208.600 ;
    END
  END r0_rd_out[154]
  PIN r0_rd_out[155]
    DIRECTION OUTPUT ;
    USE SIGNAL ;
    SHAPE ABUTMENT ;
    PORT
      LAYER metal2 ;
      RECT 89.455 208.390 89.525 208.600 ;
    END
  END r0_rd_out[155]
  PIN r0_rd_out[156]
    DIRECTION OUTPUT ;
    USE SIGNAL ;
    SHAPE ABUTMENT ;
    PORT
      LAYER metal2 ;
      RECT 90.025 208.390 90.095 208.600 ;
    END
  END r0_rd_out[156]
  PIN r0_rd_out[157]
    DIRECTION OUTPUT ;
    USE SIGNAL ;
    SHAPE ABUTMENT ;
    PORT
      LAYER metal2 ;
      RECT 90.595 208.390 90.665 208.600 ;
    END
  END r0_rd_out[157]
  PIN r0_rd_out[158]
    DIRECTION OUTPUT ;
    USE SIGNAL ;
    SHAPE ABUTMENT ;
    PORT
      LAYER metal2 ;
      RECT 91.165 208.390 91.235 208.600 ;
    END
  END r0_rd_out[158]
  PIN r0_rd_out[159]
    DIRECTION OUTPUT ;
    USE SIGNAL ;
    SHAPE ABUTMENT ;
    PORT
      LAYER metal2 ;
      RECT 91.735 208.390 91.805 208.600 ;
    END
  END r0_rd_out[159]
  PIN r0_rd_out[160]
    DIRECTION OUTPUT ;
    USE SIGNAL ;
    SHAPE ABUTMENT ;
    PORT
      LAYER metal2 ;
      RECT 92.305 208.390 92.375 208.600 ;
    END
  END r0_rd_out[160]
  PIN r0_rd_out[161]
    DIRECTION OUTPUT ;
    USE SIGNAL ;
    SHAPE ABUTMENT ;
    PORT
      LAYER metal2 ;
      RECT 92.875 208.390 92.945 208.600 ;
    END
  END r0_rd_out[161]
  PIN r0_rd_out[162]
    DIRECTION OUTPUT ;
    USE SIGNAL ;
    SHAPE ABUTMENT ;
    PORT
      LAYER metal2 ;
      RECT 93.445 208.390 93.515 208.600 ;
    END
  END r0_rd_out[162]
  PIN r0_rd_out[163]
    DIRECTION OUTPUT ;
    USE SIGNAL ;
    SHAPE ABUTMENT ;
    PORT
      LAYER metal2 ;
      RECT 94.015 208.390 94.085 208.600 ;
    END
  END r0_rd_out[163]
  PIN r0_rd_out[164]
    DIRECTION OUTPUT ;
    USE SIGNAL ;
    SHAPE ABUTMENT ;
    PORT
      LAYER metal2 ;
      RECT 94.585 208.390 94.655 208.600 ;
    END
  END r0_rd_out[164]
  PIN r0_rd_out[165]
    DIRECTION OUTPUT ;
    USE SIGNAL ;
    SHAPE ABUTMENT ;
    PORT
      LAYER metal2 ;
      RECT 95.155 208.390 95.225 208.600 ;
    END
  END r0_rd_out[165]
  PIN r0_rd_out[166]
    DIRECTION OUTPUT ;
    USE SIGNAL ;
    SHAPE ABUTMENT ;
    PORT
      LAYER metal2 ;
      RECT 95.725 208.390 95.795 208.600 ;
    END
  END r0_rd_out[166]
  PIN r0_rd_out[167]
    DIRECTION OUTPUT ;
    USE SIGNAL ;
    SHAPE ABUTMENT ;
    PORT
      LAYER metal2 ;
      RECT 96.295 208.390 96.365 208.600 ;
    END
  END r0_rd_out[167]
  PIN r0_rd_out[168]
    DIRECTION OUTPUT ;
    USE SIGNAL ;
    SHAPE ABUTMENT ;
    PORT
      LAYER metal2 ;
      RECT 96.865 208.390 96.935 208.600 ;
    END
  END r0_rd_out[168]
  PIN r0_rd_out[169]
    DIRECTION OUTPUT ;
    USE SIGNAL ;
    SHAPE ABUTMENT ;
    PORT
      LAYER metal2 ;
      RECT 97.435 208.390 97.505 208.600 ;
    END
  END r0_rd_out[169]
  PIN r0_rd_out[170]
    DIRECTION OUTPUT ;
    USE SIGNAL ;
    SHAPE ABUTMENT ;
    PORT
      LAYER metal2 ;
      RECT 98.005 208.390 98.075 208.600 ;
    END
  END r0_rd_out[170]
  PIN r0_rd_out[171]
    DIRECTION OUTPUT ;
    USE SIGNAL ;
    SHAPE ABUTMENT ;
    PORT
      LAYER metal2 ;
      RECT 98.575 208.390 98.645 208.600 ;
    END
  END r0_rd_out[171]
  PIN r0_rd_out[172]
    DIRECTION OUTPUT ;
    USE SIGNAL ;
    SHAPE ABUTMENT ;
    PORT
      LAYER metal2 ;
      RECT 99.145 208.390 99.215 208.600 ;
    END
  END r0_rd_out[172]
  PIN r0_rd_out[173]
    DIRECTION OUTPUT ;
    USE SIGNAL ;
    SHAPE ABUTMENT ;
    PORT
      LAYER metal2 ;
      RECT 99.715 208.390 99.785 208.600 ;
    END
  END r0_rd_out[173]
  PIN r0_rd_out[174]
    DIRECTION OUTPUT ;
    USE SIGNAL ;
    SHAPE ABUTMENT ;
    PORT
      LAYER metal2 ;
      RECT 100.285 208.390 100.355 208.600 ;
    END
  END r0_rd_out[174]
  PIN r0_rd_out[175]
    DIRECTION OUTPUT ;
    USE SIGNAL ;
    SHAPE ABUTMENT ;
    PORT
      LAYER metal2 ;
      RECT 100.855 208.390 100.925 208.600 ;
    END
  END r0_rd_out[175]
  PIN r0_rd_out[176]
    DIRECTION OUTPUT ;
    USE SIGNAL ;
    SHAPE ABUTMENT ;
    PORT
      LAYER metal2 ;
      RECT 101.425 208.390 101.495 208.600 ;
    END
  END r0_rd_out[176]
  PIN r0_rd_out[177]
    DIRECTION OUTPUT ;
    USE SIGNAL ;
    SHAPE ABUTMENT ;
    PORT
      LAYER metal2 ;
      RECT 101.995 208.390 102.065 208.600 ;
    END
  END r0_rd_out[177]
  PIN r0_rd_out[178]
    DIRECTION OUTPUT ;
    USE SIGNAL ;
    SHAPE ABUTMENT ;
    PORT
      LAYER metal2 ;
      RECT 102.565 208.390 102.635 208.600 ;
    END
  END r0_rd_out[178]
  PIN r0_rd_out[179]
    DIRECTION OUTPUT ;
    USE SIGNAL ;
    SHAPE ABUTMENT ;
    PORT
      LAYER metal2 ;
      RECT 103.135 208.390 103.205 208.600 ;
    END
  END r0_rd_out[179]
  PIN r0_rd_out[180]
    DIRECTION OUTPUT ;
    USE SIGNAL ;
    SHAPE ABUTMENT ;
    PORT
      LAYER metal2 ;
      RECT 103.705 208.390 103.775 208.600 ;
    END
  END r0_rd_out[180]
  PIN r0_rd_out[181]
    DIRECTION OUTPUT ;
    USE SIGNAL ;
    SHAPE ABUTMENT ;
    PORT
      LAYER metal2 ;
      RECT 104.275 208.390 104.345 208.600 ;
    END
  END r0_rd_out[181]
  PIN r0_rd_out[182]
    DIRECTION OUTPUT ;
    USE SIGNAL ;
    SHAPE ABUTMENT ;
    PORT
      LAYER metal2 ;
      RECT 104.845 208.390 104.915 208.600 ;
    END
  END r0_rd_out[182]
  PIN r0_rd_out[183]
    DIRECTION OUTPUT ;
    USE SIGNAL ;
    SHAPE ABUTMENT ;
    PORT
      LAYER metal2 ;
      RECT 105.415 208.390 105.485 208.600 ;
    END
  END r0_rd_out[183]
  PIN r0_rd_out[184]
    DIRECTION OUTPUT ;
    USE SIGNAL ;
    SHAPE ABUTMENT ;
    PORT
      LAYER metal2 ;
      RECT 105.985 208.390 106.055 208.600 ;
    END
  END r0_rd_out[184]
  PIN r0_rd_out[185]
    DIRECTION OUTPUT ;
    USE SIGNAL ;
    SHAPE ABUTMENT ;
    PORT
      LAYER metal2 ;
      RECT 106.555 208.390 106.625 208.600 ;
    END
  END r0_rd_out[185]
  PIN r0_rd_out[186]
    DIRECTION OUTPUT ;
    USE SIGNAL ;
    SHAPE ABUTMENT ;
    PORT
      LAYER metal2 ;
      RECT 107.125 208.390 107.195 208.600 ;
    END
  END r0_rd_out[186]
  PIN r0_rd_out[187]
    DIRECTION OUTPUT ;
    USE SIGNAL ;
    SHAPE ABUTMENT ;
    PORT
      LAYER metal2 ;
      RECT 107.695 208.390 107.765 208.600 ;
    END
  END r0_rd_out[187]
  PIN r0_rd_out[188]
    DIRECTION OUTPUT ;
    USE SIGNAL ;
    SHAPE ABUTMENT ;
    PORT
      LAYER metal2 ;
      RECT 108.265 208.390 108.335 208.600 ;
    END
  END r0_rd_out[188]
  PIN r0_rd_out[189]
    DIRECTION OUTPUT ;
    USE SIGNAL ;
    SHAPE ABUTMENT ;
    PORT
      LAYER metal2 ;
      RECT 108.835 208.390 108.905 208.600 ;
    END
  END r0_rd_out[189]
  PIN r0_rd_out[190]
    DIRECTION OUTPUT ;
    USE SIGNAL ;
    SHAPE ABUTMENT ;
    PORT
      LAYER metal2 ;
      RECT 109.405 208.390 109.475 208.600 ;
    END
  END r0_rd_out[190]
  PIN r0_rd_out[191]
    DIRECTION OUTPUT ;
    USE SIGNAL ;
    SHAPE ABUTMENT ;
    PORT
      LAYER metal2 ;
      RECT 109.975 208.390 110.045 208.600 ;
    END
  END r0_rd_out[191]
  PIN w0_addr_in[0]
    DIRECTION INPUT ;
    USE SIGNAL ;
    SHAPE ABUTMENT ;
    PORT
      LAYER metal3 ;
      RECT 0.000 188.965 0.210 189.035 ;
    END
  END w0_addr_in[0]
  PIN w0_addr_in[1]
    DIRECTION INPUT ;
    USE SIGNAL ;
    SHAPE ABUTMENT ;
    PORT
      LAYER metal3 ;
      RECT 0.000 190.925 0.210 190.995 ;
    END
  END w0_addr_in[1]
  PIN w0_addr_in[2]
    DIRECTION INPUT ;
    USE SIGNAL ;
    SHAPE ABUTMENT ;
    PORT
      LAYER metal3 ;
      RECT 0.000 192.885 0.210 192.955 ;
    END
  END w0_addr_in[2]
  PIN w0_addr_in[3]
    DIRECTION INPUT ;
    USE SIGNAL ;
    SHAPE ABUTMENT ;
    PORT
      LAYER metal3 ;
      RECT 119.490 188.965 119.700 189.035 ;
    END
  END w0_addr_in[3]
  PIN r0_addr_in[0]
    DIRECTION INPUT ;
    USE SIGNAL ;
    SHAPE ABUTMENT ;
    PORT
      LAYER metal3 ;
      RECT 0.000 194.845 0.210 194.915 ;
    END
  END r0_addr_in[0]
  PIN r0_addr_in[1]
    DIRECTION INPUT ;
    USE SIGNAL ;
    SHAPE ABUTMENT ;
    PORT
      LAYER metal3 ;
      RECT 0.000 196.805 0.210 196.875 ;
    END
  END r0_addr_in[1]
  PIN r0_addr_in[2]
    DIRECTION INPUT ;
    USE SIGNAL ;
    SHAPE ABUTMENT ;
    PORT
      LAYER metal3 ;
      RECT 0.000 198.765 0.210 198.835 ;
    END
  END r0_addr_in[2]
  PIN r0_addr_in[3]
    DIRECTION INPUT ;
    USE SIGNAL ;
    SHAPE ABUTMENT ;
    PORT
      LAYER metal3 ;
      RECT 119.490 192.885 119.700 192.955 ;
    END
  END r0_addr_in[3]
  PIN w0_we_in
    DIRECTION INPUT ;
    USE SIGNAL ;
    SHAPE ABUTMENT ;
    PORT
      LAYER metal2 ;
      RECT 110.545 208.390 110.615 208.600 ;
    END
  END w0_we_in
  PIN w0_ce_in
    DIRECTION INPUT ;
    USE SIGNAL ;
    SHAPE ABUTMENT ;
    PORT
      LAYER metal2 ;
      RECT 111.115 208.390 111.185 208.600 ;
    END
  END w0_ce_in
  PIN w0_clk
    DIRECTION INPUT ;
    USE SIGNAL ;
    SHAPE ABUTMENT ;
    PORT
      LAYER metal2 ;
      RECT 111.685 208.390 111.755 208.600 ;
    END
  END w0_clk
  PIN r0_ce_in
    DIRECTION INPUT ;
    USE SIGNAL ;
    SHAPE ABUTMENT ;
    PORT
      LAYER metal2 ;
      RECT 112.255 208.390 112.325 208.600 ;
    END
  END r0_ce_in
  PIN r0_clk
    DIRECTION INPUT ;
    USE SIGNAL ;
    SHAPE ABUTMENT ;
    PORT
      LAYER metal2 ;
      RECT 112.825 208.390 112.895 208.600 ;
    END
  END r0_clk
  PIN VSS
    DIRECTION INOUT ;
    USE GROUND ;
    PORT
      LAYER metal4 ;
      RECT 1.000 0.840 1.280 207.760 ;
      RECT 3.240 0.840 3.520 207.760 ;
      RECT 5.480 0.840 5.760 207.760 ;
      RECT 7.720 0.840 8.000 207.760 ;
      RECT 9.960 0.840 10.240 207.760 ;
      RECT 12.200 0.840 12.480 207.760 ;
      RECT 14.440 0.840 14.720 207.760 ;
      RECT 16.680 0.840 16.960 207.760 ;
      RECT 18.920 0.840 19.200 207.760 ;
      RECT 21.160 0.840 21.440 207.760 ;
      RECT 23.400 0.840 23.680 207.760 ;
      RECT 25.640 0.840 25.920 207.760 ;
      RECT 27.880 0.840 28.160 207.760 ;
      RECT 30.120 0.840 30.400 207.760 ;
      RECT 32.360 0.840 32.640 207.760 ;
      RECT 34.600 0.840 34.880 207.760 ;
      RECT 36.840 0.840 37.120 207.760 ;
      RECT 39.080 0.840 39.360 207.760 ;
      RECT 41.320 0.840 41.600 207.760 ;
      RECT 43.560 0.840 43.840 207.760 ;
      RECT 45.800 0.840 46.080 207.760 ;
      RECT 48.040 0.840 48.320 207.760 ;
      RECT 50.280 0.840 50.560 207.760 ;
      RECT 52.520 0.840 52.800 207.760 ;
      RECT 54.760 0.840 55.040 207.760 ;
      RECT 57.000 0.840 57.280 207.760 ;
      RECT 59.240 0.840 59.520 207.760 ;
      RECT 61.480 0.840 61.760 207.760 ;
      RECT 63.720 0.840 64.000 207.760 ;
      RECT 65.960 0.840 66.240 207.760 ;
      RECT 68.200 0.840 68.480 207.760 ;
      RECT 70.440 0.840 70.720 207.760 ;
      RECT 72.680 0.840 72.960 207.760 ;
      RECT 74.920 0.840 75.200 207.760 ;
      RECT 77.160 0.840 77.440 207.760 ;
      RECT 79.400 0.840 79.680 207.760 ;
      RECT 81.640 0.840 81.920 207.760 ;
      RECT 83.880 0.840 84.160 207.760 ;
      RECT 86.120 0.840 86.400 207.760 ;
      RECT 88.360 0.840 88.640 207.760 ;
      RECT 90.600 0.840 90.880 207.760 ;
      RECT 92.840 0.840 93.120 207.760 ;
      RECT 95.080 0.840 95.360 207.760 ;
      RECT 97.320 0.840 97.600 207.760 ;
      RECT 99.560 0.840 99.840 207.760 ;
      RECT 101.800 0.840 102.080 207.760 ;
      RECT 104.040 0.840 104.320 207.760 ;
      RECT 106.280 0.840 106.560 207.760 ;
      RECT 108.520 0.840 108.800 207.760 ;
      RECT 110.760 0.840 111.040 207.760 ;
      RECT 113.000 0.840 113.280 207.760 ;
      RECT 115.240 0.840 115.520 207.760 ;
      RECT 117.480 0.840 117.760 207.760 ;
    END
  END VSS
  PIN VDD
    DIRECTION INOUT ;
    USE POWER ;
    PORT
      LAYER metal4 ;
      RECT 1.000 0.840 1.280 207.760 ;
      RECT 3.240 0.840 3.520 207.760 ;
      RECT 5.480 0.840 5.760 207.760 ;
      RECT 7.720 0.840 8.000 207.760 ;
      RECT 9.960 0.840 10.240 207.760 ;
      RECT 12.200 0.840 12.480 207.760 ;
      RECT 14.440 0.840 14.720 207.760 ;
      RECT 16.680 0.840 16.960 207.760 ;
      RECT 18.920 0.840 19.200 207.760 ;
      RECT 21.160 0.840 21.440 207.760 ;
      RECT 23.400 0.840 23.680 207.760 ;
      RECT 25.640 0.840 25.920 207.760 ;
      RECT 27.880 0.840 28.160 207.760 ;
      RECT 30.120 0.840 30.400 207.760 ;
      RECT 32.360 0.840 32.640 207.760 ;
      RECT 34.600 0.840 34.880 207.760 ;
      RECT 36.840 0.840 37.120 207.760 ;
      RECT 39.080 0.840 39.360 207.760 ;
      RECT 41.320 0.840 41.600 207.760 ;
      RECT 43.560 0.840 43.840 207.760 ;
      RECT 45.800 0.840 46.080 207.760 ;
      RECT 48.040 0.840 48.320 207.760 ;
      RECT 50.280 0.840 50.560 207.760 ;
      RECT 52.520 0.840 52.800 207.760 ;
      RECT 54.760 0.840 55.040 207.760 ;
      RECT 57.000 0.840 57.280 207.760 ;
      RECT 59.240 0.840 59.520 207.760 ;
      RECT 61.480 0.840 61.760 207.760 ;
      RECT 63.720 0.840 64.000 207.760 ;
      RECT 65.960 0.840 66.240 207.760 ;
      RECT 68.200 0.840 68.480 207.760 ;
      RECT 70.440 0.840 70.720 207.760 ;
      RECT 72.680 0.840 72.960 207.760 ;
      RECT 74.920 0.840 75.200 207.760 ;
      RECT 77.160 0.840 77.440 207.760 ;
      RECT 79.400 0.840 79.680 207.760 ;
      RECT 81.640 0.840 81.920 207.760 ;
      RECT 83.880 0.840 84.160 207.760 ;
      RECT 86.120 0.840 86.400 207.760 ;
      RECT 88.360 0.840 88.640 207.760 ;
      RECT 90.600 0.840 90.880 207.760 ;
      RECT 92.840 0.840 93.120 207.760 ;
      RECT 95.080 0.840 95.360 207.760 ;
      RECT 97.320 0.840 97.600 207.760 ;
      RECT 99.560 0.840 99.840 207.760 ;
      RECT 101.800 0.840 102.080 207.760 ;
      RECT 104.040 0.840 104.320 207.760 ;
      RECT 106.280 0.840 106.560 207.760 ;
      RECT 108.520 0.840 108.800 207.760 ;
      RECT 110.760 0.840 111.040 207.760 ;
      RECT 113.000 0.840 113.280 207.760 ;
      RECT 115.240 0.840 115.520 207.760 ;
      RECT 117.480 0.840 117.760 207.760 ;
    END
  END VDD
  OBS
    LAYER metal1 ;
    RECT 0 0 119.700 208.600 ;
    LAYER metal2 ;
    RECT 0 0 119.700 208.600 ;
    LAYER metal3 ;
    RECT 0 0 119.700 208.600 ;
    LAYER metal4 ;
    RECT 0 0 119.700 208.600 ;
    LAYER OVERLAP ;
    RECT 0 0 119.700 208.600 ;
  END
END fakeram_192x16_1r1w

END LIBRARY
